VERSION 5.8 ;
BUSBITCHARS "[]" ;
DIVIDERCHAR "/" ;
UNITS
    DATABASE MICRONS 1000 ;
END UNITS

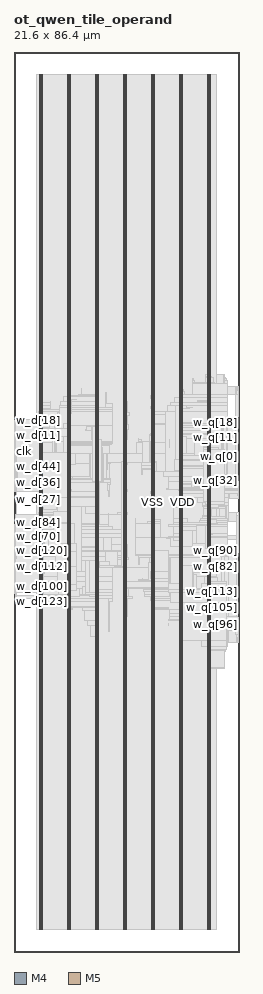
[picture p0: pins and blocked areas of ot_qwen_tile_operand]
MACRO ot_qwen_tile_operand
  FOREIGN ot_qwen_tile_operand 0 0 ;
  CLASS BLOCK ;
  SIZE 21.6 BY 86.4 ;
  PIN clk
    DIRECTION INPUT ;
    USE SIGNAL ;
    PORT
      LAYER M4 ;
        RECT  0 48.048 0.084 48.072 ;
    END
  END clk
  PIN gm_d[0]
    DIRECTION INPUT ;
    USE SIGNAL ;
    PORT
      LAYER M4 ;
        RECT  0 48.144 0.084 48.168 ;
    END
  END gm_d[0]
  PIN gm_d[1]
    DIRECTION INPUT ;
    USE SIGNAL ;
    PORT
      LAYER M4 ;
        RECT  0 48.24 0.084 48.264 ;
    END
  END gm_d[1]
  PIN gm_d[2]
    DIRECTION INPUT ;
    USE SIGNAL ;
    PORT
      LAYER M4 ;
        RECT  0 48.336 0.084 48.36 ;
    END
  END gm_d[2]
  PIN gm_d[3]
    DIRECTION INPUT ;
    USE SIGNAL ;
    PORT
      LAYER M4 ;
        RECT  0 48.432 0.084 48.456 ;
    END
  END gm_d[3]
  PIN w_d[0]
    DIRECTION INPUT ;
    USE SIGNAL ;
    PORT
      LAYER M4 ;
        RECT  0 48.528 0.084 48.552 ;
    END
  END w_d[0]
  PIN w_d[100]
    DIRECTION INPUT ;
    USE SIGNAL ;
    PORT
      LAYER M4 ;
        RECT  0 35.856 0.084 35.88 ;
    END
  END w_d[100]
  PIN w_d[101]
    DIRECTION INPUT ;
    USE SIGNAL ;
    PORT
      LAYER M4 ;
        RECT  0 35.952 0.084 35.976 ;
    END
  END w_d[101]
  PIN w_d[102]
    DIRECTION INPUT ;
    USE SIGNAL ;
    PORT
      LAYER M4 ;
        RECT  0 36.048 0.084 36.072 ;
    END
  END w_d[102]
  PIN w_d[103]
    DIRECTION INPUT ;
    USE SIGNAL ;
    PORT
      LAYER M4 ;
        RECT  0 36.144 0.084 36.168 ;
    END
  END w_d[103]
  PIN w_d[104]
    DIRECTION INPUT ;
    USE SIGNAL ;
    PORT
      LAYER M4 ;
        RECT  0 36.24 0.084 36.264 ;
    END
  END w_d[104]
  PIN w_d[105]
    DIRECTION INPUT ;
    USE SIGNAL ;
    PORT
      LAYER M4 ;
        RECT  0 36.336 0.084 36.36 ;
    END
  END w_d[105]
  PIN w_d[106]
    DIRECTION INPUT ;
    USE SIGNAL ;
    PORT
      LAYER M4 ;
        RECT  0 36.432 0.084 36.456 ;
    END
  END w_d[106]
  PIN w_d[107]
    DIRECTION INPUT ;
    USE SIGNAL ;
    PORT
      LAYER M4 ;
        RECT  0 36.528 0.084 36.552 ;
    END
  END w_d[107]
  PIN w_d[108]
    DIRECTION INPUT ;
    USE SIGNAL ;
    PORT
      LAYER M4 ;
        RECT  0 36.624 0.084 36.648 ;
    END
  END w_d[108]
  PIN w_d[109]
    DIRECTION INPUT ;
    USE SIGNAL ;
    PORT
      LAYER M4 ;
        RECT  0 36.72 0.084 36.744 ;
    END
  END w_d[109]
  PIN w_d[10]
    DIRECTION INPUT ;
    USE SIGNAL ;
    PORT
      LAYER M4 ;
        RECT  0 49.488 0.084 49.512 ;
    END
  END w_d[10]
  PIN w_d[110]
    DIRECTION INPUT ;
    USE SIGNAL ;
    PORT
      LAYER M4 ;
        RECT  0 36.816 0.084 36.84 ;
    END
  END w_d[110]
  PIN w_d[111]
    DIRECTION INPUT ;
    USE SIGNAL ;
    PORT
      LAYER M4 ;
        RECT  0 36.912 0.084 36.936 ;
    END
  END w_d[111]
  PIN w_d[112]
    DIRECTION INPUT ;
    USE SIGNAL ;
    PORT
      LAYER M4 ;
        RECT  0 37.008 0.084 37.032 ;
    END
  END w_d[112]
  PIN w_d[113]
    DIRECTION INPUT ;
    USE SIGNAL ;
    PORT
      LAYER M4 ;
        RECT  0 37.104 0.084 37.128 ;
    END
  END w_d[113]
  PIN w_d[114]
    DIRECTION INPUT ;
    USE SIGNAL ;
    PORT
      LAYER M4 ;
        RECT  0 37.2 0.084 37.224 ;
    END
  END w_d[114]
  PIN w_d[115]
    DIRECTION INPUT ;
    USE SIGNAL ;
    PORT
      LAYER M4 ;
        RECT  0 37.296 0.084 37.32 ;
    END
  END w_d[115]
  PIN w_d[116]
    DIRECTION INPUT ;
    USE SIGNAL ;
    PORT
      LAYER M4 ;
        RECT  0 37.392 0.084 37.416 ;
    END
  END w_d[116]
  PIN w_d[117]
    DIRECTION INPUT ;
    USE SIGNAL ;
    PORT
      LAYER M4 ;
        RECT  0 37.488 0.084 37.512 ;
    END
  END w_d[117]
  PIN w_d[118]
    DIRECTION INPUT ;
    USE SIGNAL ;
    PORT
      LAYER M4 ;
        RECT  0 37.584 0.084 37.608 ;
    END
  END w_d[118]
  PIN w_d[119]
    DIRECTION INPUT ;
    USE SIGNAL ;
    PORT
      LAYER M4 ;
        RECT  0 37.68 0.084 37.704 ;
    END
  END w_d[119]
  PIN w_d[11]
    DIRECTION INPUT ;
    USE SIGNAL ;
    PORT
      LAYER M4 ;
        RECT  0 49.584 0.084 49.608 ;
    END
  END w_d[11]
  PIN w_d[120]
    DIRECTION INPUT ;
    USE SIGNAL ;
    PORT
      LAYER M4 ;
        RECT  0 37.776 0.084 37.8 ;
    END
  END w_d[120]
  PIN w_d[121]
    DIRECTION INPUT ;
    USE SIGNAL ;
    PORT
      LAYER M4 ;
        RECT  0 37.872 0.084 37.896 ;
    END
  END w_d[121]
  PIN w_d[122]
    DIRECTION INPUT ;
    USE SIGNAL ;
    PORT
      LAYER M4 ;
        RECT  0 37.968 0.084 37.992 ;
    END
  END w_d[122]
  PIN w_d[123]
    DIRECTION INPUT ;
    USE SIGNAL ;
    PORT
      LAYER M4 ;
        RECT  0 34.416 0.084 34.44 ;
    END
  END w_d[123]
  PIN w_d[124]
    DIRECTION INPUT ;
    USE SIGNAL ;
    PORT
      LAYER M4 ;
        RECT  0 34.512 0.084 34.536 ;
    END
  END w_d[124]
  PIN w_d[125]
    DIRECTION INPUT ;
    USE SIGNAL ;
    PORT
      LAYER M4 ;
        RECT  0 34.608 0.084 34.632 ;
    END
  END w_d[125]
  PIN w_d[126]
    DIRECTION INPUT ;
    USE SIGNAL ;
    PORT
      LAYER M4 ;
        RECT  0 34.704 0.084 34.728 ;
    END
  END w_d[126]
  PIN w_d[127]
    DIRECTION INPUT ;
    USE SIGNAL ;
    PORT
      LAYER M4 ;
        RECT  0 34.8 0.084 34.824 ;
    END
  END w_d[127]
  PIN w_d[12]
    DIRECTION INPUT ;
    USE SIGNAL ;
    PORT
      LAYER M4 ;
        RECT  0 49.68 0.084 49.704 ;
    END
  END w_d[12]
  PIN w_d[13]
    DIRECTION INPUT ;
    USE SIGNAL ;
    PORT
      LAYER M4 ;
        RECT  0 49.776 0.084 49.8 ;
    END
  END w_d[13]
  PIN w_d[14]
    DIRECTION INPUT ;
    USE SIGNAL ;
    PORT
      LAYER M4 ;
        RECT  0 49.872 0.084 49.896 ;
    END
  END w_d[14]
  PIN w_d[15]
    DIRECTION INPUT ;
    USE SIGNAL ;
    PORT
      LAYER M4 ;
        RECT  0 49.968 0.084 49.992 ;
    END
  END w_d[15]
  PIN w_d[16]
    DIRECTION INPUT ;
    USE SIGNAL ;
    PORT
      LAYER M4 ;
        RECT  0 50.064 0.084 50.088 ;
    END
  END w_d[16]
  PIN w_d[17]
    DIRECTION INPUT ;
    USE SIGNAL ;
    PORT
      LAYER M4 ;
        RECT  0 50.16 0.084 50.184 ;
    END
  END w_d[17]
  PIN w_d[18]
    DIRECTION INPUT ;
    USE SIGNAL ;
    PORT
      LAYER M4 ;
        RECT  0 50.256 0.084 50.28 ;
    END
  END w_d[18]
  PIN w_d[19]
    DIRECTION INPUT ;
    USE SIGNAL ;
    PORT
      LAYER M4 ;
        RECT  0 50.352 0.084 50.376 ;
    END
  END w_d[19]
  PIN w_d[1]
    DIRECTION INPUT ;
    USE SIGNAL ;
    PORT
      LAYER M4 ;
        RECT  0 48.624 0.084 48.648 ;
    END
  END w_d[1]
  PIN w_d[20]
    DIRECTION INPUT ;
    USE SIGNAL ;
    PORT
      LAYER M4 ;
        RECT  0 50.448 0.084 50.472 ;
    END
  END w_d[20]
  PIN w_d[21]
    DIRECTION INPUT ;
    USE SIGNAL ;
    PORT
      LAYER M4 ;
        RECT  0 50.544 0.084 50.568 ;
    END
  END w_d[21]
  PIN w_d[22]
    DIRECTION INPUT ;
    USE SIGNAL ;
    PORT
      LAYER M4 ;
        RECT  0 50.64 0.084 50.664 ;
    END
  END w_d[22]
  PIN w_d[23]
    DIRECTION INPUT ;
    USE SIGNAL ;
    PORT
      LAYER M4 ;
        RECT  0 50.736 0.084 50.76 ;
    END
  END w_d[23]
  PIN w_d[24]
    DIRECTION INPUT ;
    USE SIGNAL ;
    PORT
      LAYER M4 ;
        RECT  0 50.832 0.084 50.856 ;
    END
  END w_d[24]
  PIN w_d[25]
    DIRECTION INPUT ;
    USE SIGNAL ;
    PORT
      LAYER M4 ;
        RECT  0 50.928 0.084 50.952 ;
    END
  END w_d[25]
  PIN w_d[26]
    DIRECTION INPUT ;
    USE SIGNAL ;
    PORT
      LAYER M4 ;
        RECT  0 51.024 0.084 51.048 ;
    END
  END w_d[26]
  PIN w_d[27]
    DIRECTION INPUT ;
    USE SIGNAL ;
    PORT
      LAYER M4 ;
        RECT  0 44.208 0.084 44.232 ;
    END
  END w_d[27]
  PIN w_d[28]
    DIRECTION INPUT ;
    USE SIGNAL ;
    PORT
      LAYER M4 ;
        RECT  0 44.304 0.084 44.328 ;
    END
  END w_d[28]
  PIN w_d[29]
    DIRECTION INPUT ;
    USE SIGNAL ;
    PORT
      LAYER M4 ;
        RECT  0 44.4 0.084 44.424 ;
    END
  END w_d[29]
  PIN w_d[2]
    DIRECTION INPUT ;
    USE SIGNAL ;
    PORT
      LAYER M4 ;
        RECT  0 48.72 0.084 48.744 ;
    END
  END w_d[2]
  PIN w_d[30]
    DIRECTION INPUT ;
    USE SIGNAL ;
    PORT
      LAYER M4 ;
        RECT  0 44.496 0.084 44.52 ;
    END
  END w_d[30]
  PIN w_d[31]
    DIRECTION INPUT ;
    USE SIGNAL ;
    PORT
      LAYER M4 ;
        RECT  0 44.592 0.084 44.616 ;
    END
  END w_d[31]
  PIN w_d[32]
    DIRECTION INPUT ;
    USE SIGNAL ;
    PORT
      LAYER M4 ;
        RECT  0 44.688 0.084 44.712 ;
    END
  END w_d[32]
  PIN w_d[33]
    DIRECTION INPUT ;
    USE SIGNAL ;
    PORT
      LAYER M4 ;
        RECT  0 44.784 0.084 44.808 ;
    END
  END w_d[33]
  PIN w_d[34]
    DIRECTION INPUT ;
    USE SIGNAL ;
    PORT
      LAYER M4 ;
        RECT  0 44.88 0.084 44.904 ;
    END
  END w_d[34]
  PIN w_d[35]
    DIRECTION INPUT ;
    USE SIGNAL ;
    PORT
      LAYER M4 ;
        RECT  0 44.976 0.084 45 ;
    END
  END w_d[35]
  PIN w_d[36]
    DIRECTION INPUT ;
    USE SIGNAL ;
    PORT
      LAYER M4 ;
        RECT  0 45.072 0.084 45.096 ;
    END
  END w_d[36]
  PIN w_d[37]
    DIRECTION INPUT ;
    USE SIGNAL ;
    PORT
      LAYER M4 ;
        RECT  0 45.168 0.084 45.192 ;
    END
  END w_d[37]
  PIN w_d[38]
    DIRECTION INPUT ;
    USE SIGNAL ;
    PORT
      LAYER M4 ;
        RECT  0 45.264 0.084 45.288 ;
    END
  END w_d[38]
  PIN w_d[39]
    DIRECTION INPUT ;
    USE SIGNAL ;
    PORT
      LAYER M4 ;
        RECT  0 45.36 0.084 45.384 ;
    END
  END w_d[39]
  PIN w_d[3]
    DIRECTION INPUT ;
    USE SIGNAL ;
    PORT
      LAYER M4 ;
        RECT  0 48.816 0.084 48.84 ;
    END
  END w_d[3]
  PIN w_d[40]
    DIRECTION INPUT ;
    USE SIGNAL ;
    PORT
      LAYER M4 ;
        RECT  0 45.456 0.084 45.48 ;
    END
  END w_d[40]
  PIN w_d[41]
    DIRECTION INPUT ;
    USE SIGNAL ;
    PORT
      LAYER M4 ;
        RECT  0 45.552 0.084 45.576 ;
    END
  END w_d[41]
  PIN w_d[42]
    DIRECTION INPUT ;
    USE SIGNAL ;
    PORT
      LAYER M4 ;
        RECT  0 45.648 0.084 45.672 ;
    END
  END w_d[42]
  PIN w_d[43]
    DIRECTION INPUT ;
    USE SIGNAL ;
    PORT
      LAYER M4 ;
        RECT  0 45.744 0.084 45.768 ;
    END
  END w_d[43]
  PIN w_d[44]
    DIRECTION INPUT ;
    USE SIGNAL ;
    PORT
      LAYER M4 ;
        RECT  0 45.84 0.084 45.864 ;
    END
  END w_d[44]
  PIN w_d[45]
    DIRECTION INPUT ;
    USE SIGNAL ;
    PORT
      LAYER M4 ;
        RECT  0 45.936 0.084 45.96 ;
    END
  END w_d[45]
  PIN w_d[46]
    DIRECTION INPUT ;
    USE SIGNAL ;
    PORT
      LAYER M4 ;
        RECT  0 46.032 0.084 46.056 ;
    END
  END w_d[46]
  PIN w_d[47]
    DIRECTION INPUT ;
    USE SIGNAL ;
    PORT
      LAYER M4 ;
        RECT  0 46.128 0.084 46.152 ;
    END
  END w_d[47]
  PIN w_d[48]
    DIRECTION INPUT ;
    USE SIGNAL ;
    PORT
      LAYER M4 ;
        RECT  0 46.224 0.084 46.248 ;
    END
  END w_d[48]
  PIN w_d[49]
    DIRECTION INPUT ;
    USE SIGNAL ;
    PORT
      LAYER M4 ;
        RECT  0 46.32 0.084 46.344 ;
    END
  END w_d[49]
  PIN w_d[4]
    DIRECTION INPUT ;
    USE SIGNAL ;
    PORT
      LAYER M4 ;
        RECT  0 48.912 0.084 48.936 ;
    END
  END w_d[4]
  PIN w_d[50]
    DIRECTION INPUT ;
    USE SIGNAL ;
    PORT
      LAYER M4 ;
        RECT  0 46.416 0.084 46.44 ;
    END
  END w_d[50]
  PIN w_d[51]
    DIRECTION INPUT ;
    USE SIGNAL ;
    PORT
      LAYER M4 ;
        RECT  0 46.512 0.084 46.536 ;
    END
  END w_d[51]
  PIN w_d[52]
    DIRECTION INPUT ;
    USE SIGNAL ;
    PORT
      LAYER M4 ;
        RECT  0 46.608 0.084 46.632 ;
    END
  END w_d[52]
  PIN w_d[53]
    DIRECTION INPUT ;
    USE SIGNAL ;
    PORT
      LAYER M4 ;
        RECT  0 46.704 0.084 46.728 ;
    END
  END w_d[53]
  PIN w_d[54]
    DIRECTION INPUT ;
    USE SIGNAL ;
    PORT
      LAYER M4 ;
        RECT  0 46.8 0.084 46.824 ;
    END
  END w_d[54]
  PIN w_d[55]
    DIRECTION INPUT ;
    USE SIGNAL ;
    PORT
      LAYER M4 ;
        RECT  0 46.896 0.084 46.92 ;
    END
  END w_d[55]
  PIN w_d[56]
    DIRECTION INPUT ;
    USE SIGNAL ;
    PORT
      LAYER M4 ;
        RECT  0 46.992 0.084 47.016 ;
    END
  END w_d[56]
  PIN w_d[57]
    DIRECTION INPUT ;
    USE SIGNAL ;
    PORT
      LAYER M4 ;
        RECT  0 47.088 0.084 47.112 ;
    END
  END w_d[57]
  PIN w_d[58]
    DIRECTION INPUT ;
    USE SIGNAL ;
    PORT
      LAYER M4 ;
        RECT  0 47.184 0.084 47.208 ;
    END
  END w_d[58]
  PIN w_d[59]
    DIRECTION INPUT ;
    USE SIGNAL ;
    PORT
      LAYER M4 ;
        RECT  0 38.064 0.084 38.088 ;
    END
  END w_d[59]
  PIN w_d[5]
    DIRECTION INPUT ;
    USE SIGNAL ;
    PORT
      LAYER M4 ;
        RECT  0 49.008 0.084 49.032 ;
    END
  END w_d[5]
  PIN w_d[60]
    DIRECTION INPUT ;
    USE SIGNAL ;
    PORT
      LAYER M4 ;
        RECT  0 38.16 0.084 38.184 ;
    END
  END w_d[60]
  PIN w_d[61]
    DIRECTION INPUT ;
    USE SIGNAL ;
    PORT
      LAYER M4 ;
        RECT  0 38.256 0.084 38.28 ;
    END
  END w_d[61]
  PIN w_d[62]
    DIRECTION INPUT ;
    USE SIGNAL ;
    PORT
      LAYER M4 ;
        RECT  0 38.352 0.084 38.376 ;
    END
  END w_d[62]
  PIN w_d[63]
    DIRECTION INPUT ;
    USE SIGNAL ;
    PORT
      LAYER M4 ;
        RECT  0 38.448 0.084 38.472 ;
    END
  END w_d[63]
  PIN w_d[64]
    DIRECTION INPUT ;
    USE SIGNAL ;
    PORT
      LAYER M4 ;
        RECT  0 38.544 0.084 38.568 ;
    END
  END w_d[64]
  PIN w_d[65]
    DIRECTION INPUT ;
    USE SIGNAL ;
    PORT
      LAYER M4 ;
        RECT  0 38.64 0.084 38.664 ;
    END
  END w_d[65]
  PIN w_d[66]
    DIRECTION INPUT ;
    USE SIGNAL ;
    PORT
      LAYER M4 ;
        RECT  0 38.736 0.084 38.76 ;
    END
  END w_d[66]
  PIN w_d[67]
    DIRECTION INPUT ;
    USE SIGNAL ;
    PORT
      LAYER M4 ;
        RECT  0 38.832 0.084 38.856 ;
    END
  END w_d[67]
  PIN w_d[68]
    DIRECTION INPUT ;
    USE SIGNAL ;
    PORT
      LAYER M4 ;
        RECT  0 38.928 0.084 38.952 ;
    END
  END w_d[68]
  PIN w_d[69]
    DIRECTION INPUT ;
    USE SIGNAL ;
    PORT
      LAYER M4 ;
        RECT  0 39.024 0.084 39.048 ;
    END
  END w_d[69]
  PIN w_d[6]
    DIRECTION INPUT ;
    USE SIGNAL ;
    PORT
      LAYER M4 ;
        RECT  0 49.104 0.084 49.128 ;
    END
  END w_d[6]
  PIN w_d[70]
    DIRECTION INPUT ;
    USE SIGNAL ;
    PORT
      LAYER M4 ;
        RECT  0 39.12 0.084 39.144 ;
    END
  END w_d[70]
  PIN w_d[71]
    DIRECTION INPUT ;
    USE SIGNAL ;
    PORT
      LAYER M4 ;
        RECT  0 39.216 0.084 39.24 ;
    END
  END w_d[71]
  PIN w_d[72]
    DIRECTION INPUT ;
    USE SIGNAL ;
    PORT
      LAYER M4 ;
        RECT  0 39.312 0.084 39.336 ;
    END
  END w_d[72]
  PIN w_d[73]
    DIRECTION INPUT ;
    USE SIGNAL ;
    PORT
      LAYER M4 ;
        RECT  0 39.408 0.084 39.432 ;
    END
  END w_d[73]
  PIN w_d[74]
    DIRECTION INPUT ;
    USE SIGNAL ;
    PORT
      LAYER M4 ;
        RECT  0 39.504 0.084 39.528 ;
    END
  END w_d[74]
  PIN w_d[75]
    DIRECTION INPUT ;
    USE SIGNAL ;
    PORT
      LAYER M4 ;
        RECT  0 39.6 0.084 39.624 ;
    END
  END w_d[75]
  PIN w_d[76]
    DIRECTION INPUT ;
    USE SIGNAL ;
    PORT
      LAYER M4 ;
        RECT  0 39.696 0.084 39.72 ;
    END
  END w_d[76]
  PIN w_d[77]
    DIRECTION INPUT ;
    USE SIGNAL ;
    PORT
      LAYER M4 ;
        RECT  0 39.792 0.084 39.816 ;
    END
  END w_d[77]
  PIN w_d[78]
    DIRECTION INPUT ;
    USE SIGNAL ;
    PORT
      LAYER M4 ;
        RECT  0 39.888 0.084 39.912 ;
    END
  END w_d[78]
  PIN w_d[79]
    DIRECTION INPUT ;
    USE SIGNAL ;
    PORT
      LAYER M4 ;
        RECT  0 39.984 0.084 40.008 ;
    END
  END w_d[79]
  PIN w_d[7]
    DIRECTION INPUT ;
    USE SIGNAL ;
    PORT
      LAYER M4 ;
        RECT  0 49.2 0.084 49.224 ;
    END
  END w_d[7]
  PIN w_d[80]
    DIRECTION INPUT ;
    USE SIGNAL ;
    PORT
      LAYER M4 ;
        RECT  0 40.08 0.084 40.104 ;
    END
  END w_d[80]
  PIN w_d[81]
    DIRECTION INPUT ;
    USE SIGNAL ;
    PORT
      LAYER M4 ;
        RECT  0 40.176 0.084 40.2 ;
    END
  END w_d[81]
  PIN w_d[82]
    DIRECTION INPUT ;
    USE SIGNAL ;
    PORT
      LAYER M4 ;
        RECT  0 40.272 0.084 40.296 ;
    END
  END w_d[82]
  PIN w_d[83]
    DIRECTION INPUT ;
    USE SIGNAL ;
    PORT
      LAYER M4 ;
        RECT  0 40.368 0.084 40.392 ;
    END
  END w_d[83]
  PIN w_d[84]
    DIRECTION INPUT ;
    USE SIGNAL ;
    PORT
      LAYER M4 ;
        RECT  0 40.464 0.084 40.488 ;
    END
  END w_d[84]
  PIN w_d[85]
    DIRECTION INPUT ;
    USE SIGNAL ;
    PORT
      LAYER M4 ;
        RECT  0 40.56 0.084 40.584 ;
    END
  END w_d[85]
  PIN w_d[86]
    DIRECTION INPUT ;
    USE SIGNAL ;
    PORT
      LAYER M4 ;
        RECT  0 40.656 0.084 40.68 ;
    END
  END w_d[86]
  PIN w_d[87]
    DIRECTION INPUT ;
    USE SIGNAL ;
    PORT
      LAYER M4 ;
        RECT  0 40.752 0.084 40.776 ;
    END
  END w_d[87]
  PIN w_d[88]
    DIRECTION INPUT ;
    USE SIGNAL ;
    PORT
      LAYER M4 ;
        RECT  0 40.848 0.084 40.872 ;
    END
  END w_d[88]
  PIN w_d[89]
    DIRECTION INPUT ;
    USE SIGNAL ;
    PORT
      LAYER M4 ;
        RECT  0 40.944 0.084 40.968 ;
    END
  END w_d[89]
  PIN w_d[8]
    DIRECTION INPUT ;
    USE SIGNAL ;
    PORT
      LAYER M4 ;
        RECT  0 49.296 0.084 49.32 ;
    END
  END w_d[8]
  PIN w_d[90]
    DIRECTION INPUT ;
    USE SIGNAL ;
    PORT
      LAYER M4 ;
        RECT  0 41.04 0.084 41.064 ;
    END
  END w_d[90]
  PIN w_d[91]
    DIRECTION INPUT ;
    USE SIGNAL ;
    PORT
      LAYER M4 ;
        RECT  0 34.992 0.084 35.016 ;
    END
  END w_d[91]
  PIN w_d[92]
    DIRECTION INPUT ;
    USE SIGNAL ;
    PORT
      LAYER M4 ;
        RECT  0 35.088 0.084 35.112 ;
    END
  END w_d[92]
  PIN w_d[93]
    DIRECTION INPUT ;
    USE SIGNAL ;
    PORT
      LAYER M4 ;
        RECT  0 35.184 0.084 35.208 ;
    END
  END w_d[93]
  PIN w_d[94]
    DIRECTION INPUT ;
    USE SIGNAL ;
    PORT
      LAYER M4 ;
        RECT  0 35.28 0.084 35.304 ;
    END
  END w_d[94]
  PIN w_d[95]
    DIRECTION INPUT ;
    USE SIGNAL ;
    PORT
      LAYER M4 ;
        RECT  0 35.376 0.084 35.4 ;
    END
  END w_d[95]
  PIN w_d[96]
    DIRECTION INPUT ;
    USE SIGNAL ;
    PORT
      LAYER M4 ;
        RECT  0 35.472 0.084 35.496 ;
    END
  END w_d[96]
  PIN w_d[97]
    DIRECTION INPUT ;
    USE SIGNAL ;
    PORT
      LAYER M4 ;
        RECT  0 35.568 0.084 35.592 ;
    END
  END w_d[97]
  PIN w_d[98]
    DIRECTION INPUT ;
    USE SIGNAL ;
    PORT
      LAYER M4 ;
        RECT  0 35.664 0.084 35.688 ;
    END
  END w_d[98]
  PIN w_d[99]
    DIRECTION INPUT ;
    USE SIGNAL ;
    PORT
      LAYER M4 ;
        RECT  0 35.76 0.084 35.784 ;
    END
  END w_d[99]
  PIN w_d[9]
    DIRECTION INPUT ;
    USE SIGNAL ;
    PORT
      LAYER M4 ;
        RECT  0 49.392 0.084 49.416 ;
    END
  END w_d[9]
  PIN w_q[0]
    DIRECTION OUTPUT ;
    USE SIGNAL ;
    PORT
      LAYER M4 ;
        RECT  21.516 48.336 21.6 48.36 ;
    END
  END w_q[0]
  PIN w_q[100]
    DIRECTION OUTPUT ;
    USE SIGNAL ;
    PORT
      LAYER M4 ;
        RECT  21.516 32.592 21.6 32.616 ;
    END
  END w_q[100]
  PIN w_q[101]
    DIRECTION OUTPUT ;
    USE SIGNAL ;
    PORT
      LAYER M4 ;
        RECT  21.516 32.688 21.6 32.712 ;
    END
  END w_q[101]
  PIN w_q[102]
    DIRECTION OUTPUT ;
    USE SIGNAL ;
    PORT
      LAYER M4 ;
        RECT  21.516 32.784 21.6 32.808 ;
    END
  END w_q[102]
  PIN w_q[103]
    DIRECTION OUTPUT ;
    USE SIGNAL ;
    PORT
      LAYER M4 ;
        RECT  21.516 32.88 21.6 32.904 ;
    END
  END w_q[103]
  PIN w_q[104]
    DIRECTION OUTPUT ;
    USE SIGNAL ;
    PORT
      LAYER M4 ;
        RECT  21.516 32.976 21.6 33 ;
    END
  END w_q[104]
  PIN w_q[105]
    DIRECTION OUTPUT ;
    USE SIGNAL ;
    PORT
      LAYER M4 ;
        RECT  21.516 33.072 21.6 33.096 ;
    END
  END w_q[105]
  PIN w_q[106]
    DIRECTION OUTPUT ;
    USE SIGNAL ;
    PORT
      LAYER M4 ;
        RECT  21.516 33.168 21.6 33.192 ;
    END
  END w_q[106]
  PIN w_q[107]
    DIRECTION OUTPUT ;
    USE SIGNAL ;
    PORT
      LAYER M4 ;
        RECT  21.516 33.264 21.6 33.288 ;
    END
  END w_q[107]
  PIN w_q[108]
    DIRECTION OUTPUT ;
    USE SIGNAL ;
    PORT
      LAYER M4 ;
        RECT  21.516 33.36 21.6 33.384 ;
    END
  END w_q[108]
  PIN w_q[109]
    DIRECTION OUTPUT ;
    USE SIGNAL ;
    PORT
      LAYER M4 ;
        RECT  21.516 33.456 21.6 33.48 ;
    END
  END w_q[109]
  PIN w_q[10]
    DIRECTION OUTPUT ;
    USE SIGNAL ;
    PORT
      LAYER M4 ;
        RECT  21.516 49.296 21.6 49.32 ;
    END
  END w_q[10]
  PIN w_q[110]
    DIRECTION OUTPUT ;
    USE SIGNAL ;
    PORT
      LAYER M4 ;
        RECT  21.516 33.552 21.6 33.576 ;
    END
  END w_q[110]
  PIN w_q[111]
    DIRECTION OUTPUT ;
    USE SIGNAL ;
    PORT
      LAYER M4 ;
        RECT  21.516 33.648 21.6 33.672 ;
    END
  END w_q[111]
  PIN w_q[112]
    DIRECTION OUTPUT ;
    USE SIGNAL ;
    PORT
      LAYER M4 ;
        RECT  21.516 33.744 21.6 33.768 ;
    END
  END w_q[112]
  PIN w_q[113]
    DIRECTION OUTPUT ;
    USE SIGNAL ;
    PORT
      LAYER M4 ;
        RECT  21.516 33.84 21.6 33.864 ;
    END
  END w_q[113]
  PIN w_q[114]
    DIRECTION OUTPUT ;
    USE SIGNAL ;
    PORT
      LAYER M4 ;
        RECT  21.516 33.936 21.6 33.96 ;
    END
  END w_q[114]
  PIN w_q[115]
    DIRECTION OUTPUT ;
    USE SIGNAL ;
    PORT
      LAYER M4 ;
        RECT  21.516 34.032 21.6 34.056 ;
    END
  END w_q[115]
  PIN w_q[116]
    DIRECTION OUTPUT ;
    USE SIGNAL ;
    PORT
      LAYER M4 ;
        RECT  21.516 34.128 21.6 34.152 ;
    END
  END w_q[116]
  PIN w_q[117]
    DIRECTION OUTPUT ;
    USE SIGNAL ;
    PORT
      LAYER M4 ;
        RECT  21.516 34.224 21.6 34.248 ;
    END
  END w_q[117]
  PIN w_q[118]
    DIRECTION OUTPUT ;
    USE SIGNAL ;
    PORT
      LAYER M4 ;
        RECT  21.516 34.32 21.6 34.344 ;
    END
  END w_q[118]
  PIN w_q[119]
    DIRECTION OUTPUT ;
    USE SIGNAL ;
    PORT
      LAYER M4 ;
        RECT  21.516 34.416 21.6 34.44 ;
    END
  END w_q[119]
  PIN w_q[11]
    DIRECTION OUTPUT ;
    USE SIGNAL ;
    PORT
      LAYER M4 ;
        RECT  21.516 49.392 21.6 49.416 ;
    END
  END w_q[11]
  PIN w_q[120]
    DIRECTION OUTPUT ;
    USE SIGNAL ;
    PORT
      LAYER M4 ;
        RECT  21.516 34.512 21.6 34.536 ;
    END
  END w_q[120]
  PIN w_q[121]
    DIRECTION OUTPUT ;
    USE SIGNAL ;
    PORT
      LAYER M4 ;
        RECT  21.516 34.608 21.6 34.632 ;
    END
  END w_q[121]
  PIN w_q[122]
    DIRECTION OUTPUT ;
    USE SIGNAL ;
    PORT
      LAYER M4 ;
        RECT  21.516 34.704 21.6 34.728 ;
    END
  END w_q[122]
  PIN w_q[123]
    DIRECTION OUTPUT ;
    USE SIGNAL ;
    PORT
      LAYER M4 ;
        RECT  21.516 34.8 21.6 34.824 ;
    END
  END w_q[123]
  PIN w_q[124]
    DIRECTION OUTPUT ;
    USE SIGNAL ;
    PORT
      LAYER M4 ;
        RECT  21.516 34.896 21.6 34.92 ;
    END
  END w_q[124]
  PIN w_q[125]
    DIRECTION OUTPUT ;
    USE SIGNAL ;
    PORT
      LAYER M4 ;
        RECT  21.516 34.992 21.6 35.016 ;
    END
  END w_q[125]
  PIN w_q[126]
    DIRECTION OUTPUT ;
    USE SIGNAL ;
    PORT
      LAYER M4 ;
        RECT  21.516 35.088 21.6 35.112 ;
    END
  END w_q[126]
  PIN w_q[127]
    DIRECTION OUTPUT ;
    USE SIGNAL ;
    PORT
      LAYER M4 ;
        RECT  21.516 35.184 21.6 35.208 ;
    END
  END w_q[127]
  PIN w_q[12]
    DIRECTION OUTPUT ;
    USE SIGNAL ;
    PORT
      LAYER M4 ;
        RECT  21.516 49.488 21.6 49.512 ;
    END
  END w_q[12]
  PIN w_q[13]
    DIRECTION OUTPUT ;
    USE SIGNAL ;
    PORT
      LAYER M4 ;
        RECT  21.516 49.584 21.6 49.608 ;
    END
  END w_q[13]
  PIN w_q[14]
    DIRECTION OUTPUT ;
    USE SIGNAL ;
    PORT
      LAYER M4 ;
        RECT  21.516 49.68 21.6 49.704 ;
    END
  END w_q[14]
  PIN w_q[15]
    DIRECTION OUTPUT ;
    USE SIGNAL ;
    PORT
      LAYER M4 ;
        RECT  21.516 49.776 21.6 49.8 ;
    END
  END w_q[15]
  PIN w_q[16]
    DIRECTION OUTPUT ;
    USE SIGNAL ;
    PORT
      LAYER M4 ;
        RECT  21.516 49.872 21.6 49.896 ;
    END
  END w_q[16]
  PIN w_q[17]
    DIRECTION OUTPUT ;
    USE SIGNAL ;
    PORT
      LAYER M4 ;
        RECT  21.516 49.968 21.6 49.992 ;
    END
  END w_q[17]
  PIN w_q[18]
    DIRECTION OUTPUT ;
    USE SIGNAL ;
    PORT
      LAYER M4 ;
        RECT  21.516 50.064 21.6 50.088 ;
    END
  END w_q[18]
  PIN w_q[19]
    DIRECTION OUTPUT ;
    USE SIGNAL ;
    PORT
      LAYER M4 ;
        RECT  21.516 50.16 21.6 50.184 ;
    END
  END w_q[19]
  PIN w_q[1]
    DIRECTION OUTPUT ;
    USE SIGNAL ;
    PORT
      LAYER M4 ;
        RECT  21.516 48.432 21.6 48.456 ;
    END
  END w_q[1]
  PIN w_q[20]
    DIRECTION OUTPUT ;
    USE SIGNAL ;
    PORT
      LAYER M4 ;
        RECT  21.516 50.256 21.6 50.28 ;
    END
  END w_q[20]
  PIN w_q[21]
    DIRECTION OUTPUT ;
    USE SIGNAL ;
    PORT
      LAYER M4 ;
        RECT  21.516 50.352 21.6 50.376 ;
    END
  END w_q[21]
  PIN w_q[22]
    DIRECTION OUTPUT ;
    USE SIGNAL ;
    PORT
      LAYER M4 ;
        RECT  21.516 50.448 21.6 50.472 ;
    END
  END w_q[22]
  PIN w_q[23]
    DIRECTION OUTPUT ;
    USE SIGNAL ;
    PORT
      LAYER M4 ;
        RECT  21.516 50.544 21.6 50.568 ;
    END
  END w_q[23]
  PIN w_q[24]
    DIRECTION OUTPUT ;
    USE SIGNAL ;
    PORT
      LAYER M4 ;
        RECT  21.516 50.64 21.6 50.664 ;
    END
  END w_q[24]
  PIN w_q[25]
    DIRECTION OUTPUT ;
    USE SIGNAL ;
    PORT
      LAYER M4 ;
        RECT  21.516 50.736 21.6 50.76 ;
    END
  END w_q[25]
  PIN w_q[26]
    DIRECTION OUTPUT ;
    USE SIGNAL ;
    PORT
      LAYER M4 ;
        RECT  21.516 50.832 21.6 50.856 ;
    END
  END w_q[26]
  PIN w_q[27]
    DIRECTION OUTPUT ;
    USE SIGNAL ;
    PORT
      LAYER M4 ;
        RECT  21.516 50.928 21.6 50.952 ;
    END
  END w_q[27]
  PIN w_q[28]
    DIRECTION OUTPUT ;
    USE SIGNAL ;
    PORT
      LAYER M4 ;
        RECT  21.516 51.024 21.6 51.048 ;
    END
  END w_q[28]
  PIN w_q[29]
    DIRECTION OUTPUT ;
    USE SIGNAL ;
    PORT
      LAYER M4 ;
        RECT  21.516 51.12 21.6 51.144 ;
    END
  END w_q[29]
  PIN w_q[2]
    DIRECTION OUTPUT ;
    USE SIGNAL ;
    PORT
      LAYER M4 ;
        RECT  21.516 48.528 21.6 48.552 ;
    END
  END w_q[2]
  PIN w_q[30]
    DIRECTION OUTPUT ;
    USE SIGNAL ;
    PORT
      LAYER M4 ;
        RECT  21.516 51.216 21.6 51.24 ;
    END
  END w_q[30]
  PIN w_q[31]
    DIRECTION OUTPUT ;
    USE SIGNAL ;
    PORT
      LAYER M4 ;
        RECT  21.516 51.312 21.6 51.336 ;
    END
  END w_q[31]
  PIN w_q[32]
    DIRECTION OUTPUT ;
    USE SIGNAL ;
    PORT
      LAYER M4 ;
        RECT  21.516 45.264 21.6 45.288 ;
    END
  END w_q[32]
  PIN w_q[33]
    DIRECTION OUTPUT ;
    USE SIGNAL ;
    PORT
      LAYER M4 ;
        RECT  21.516 45.36 21.6 45.384 ;
    END
  END w_q[33]
  PIN w_q[34]
    DIRECTION OUTPUT ;
    USE SIGNAL ;
    PORT
      LAYER M4 ;
        RECT  21.516 45.456 21.6 45.48 ;
    END
  END w_q[34]
  PIN w_q[35]
    DIRECTION OUTPUT ;
    USE SIGNAL ;
    PORT
      LAYER M4 ;
        RECT  21.516 45.552 21.6 45.576 ;
    END
  END w_q[35]
  PIN w_q[36]
    DIRECTION OUTPUT ;
    USE SIGNAL ;
    PORT
      LAYER M4 ;
        RECT  21.516 45.648 21.6 45.672 ;
    END
  END w_q[36]
  PIN w_q[37]
    DIRECTION OUTPUT ;
    USE SIGNAL ;
    PORT
      LAYER M4 ;
        RECT  21.516 45.744 21.6 45.768 ;
    END
  END w_q[37]
  PIN w_q[38]
    DIRECTION OUTPUT ;
    USE SIGNAL ;
    PORT
      LAYER M4 ;
        RECT  21.516 45.84 21.6 45.864 ;
    END
  END w_q[38]
  PIN w_q[39]
    DIRECTION OUTPUT ;
    USE SIGNAL ;
    PORT
      LAYER M4 ;
        RECT  21.516 45.936 21.6 45.96 ;
    END
  END w_q[39]
  PIN w_q[3]
    DIRECTION OUTPUT ;
    USE SIGNAL ;
    PORT
      LAYER M4 ;
        RECT  21.516 48.624 21.6 48.648 ;
    END
  END w_q[3]
  PIN w_q[40]
    DIRECTION OUTPUT ;
    USE SIGNAL ;
    PORT
      LAYER M4 ;
        RECT  21.516 46.032 21.6 46.056 ;
    END
  END w_q[40]
  PIN w_q[41]
    DIRECTION OUTPUT ;
    USE SIGNAL ;
    PORT
      LAYER M4 ;
        RECT  21.516 46.128 21.6 46.152 ;
    END
  END w_q[41]
  PIN w_q[42]
    DIRECTION OUTPUT ;
    USE SIGNAL ;
    PORT
      LAYER M4 ;
        RECT  21.516 46.224 21.6 46.248 ;
    END
  END w_q[42]
  PIN w_q[43]
    DIRECTION OUTPUT ;
    USE SIGNAL ;
    PORT
      LAYER M4 ;
        RECT  21.516 46.32 21.6 46.344 ;
    END
  END w_q[43]
  PIN w_q[44]
    DIRECTION OUTPUT ;
    USE SIGNAL ;
    PORT
      LAYER M4 ;
        RECT  21.516 46.416 21.6 46.44 ;
    END
  END w_q[44]
  PIN w_q[45]
    DIRECTION OUTPUT ;
    USE SIGNAL ;
    PORT
      LAYER M4 ;
        RECT  21.516 46.512 21.6 46.536 ;
    END
  END w_q[45]
  PIN w_q[46]
    DIRECTION OUTPUT ;
    USE SIGNAL ;
    PORT
      LAYER M4 ;
        RECT  21.516 46.608 21.6 46.632 ;
    END
  END w_q[46]
  PIN w_q[47]
    DIRECTION OUTPUT ;
    USE SIGNAL ;
    PORT
      LAYER M4 ;
        RECT  21.516 46.704 21.6 46.728 ;
    END
  END w_q[47]
  PIN w_q[48]
    DIRECTION OUTPUT ;
    USE SIGNAL ;
    PORT
      LAYER M4 ;
        RECT  21.516 46.8 21.6 46.824 ;
    END
  END w_q[48]
  PIN w_q[49]
    DIRECTION OUTPUT ;
    USE SIGNAL ;
    PORT
      LAYER M4 ;
        RECT  21.516 46.896 21.6 46.92 ;
    END
  END w_q[49]
  PIN w_q[4]
    DIRECTION OUTPUT ;
    USE SIGNAL ;
    PORT
      LAYER M4 ;
        RECT  21.516 48.72 21.6 48.744 ;
    END
  END w_q[4]
  PIN w_q[50]
    DIRECTION OUTPUT ;
    USE SIGNAL ;
    PORT
      LAYER M4 ;
        RECT  21.516 46.992 21.6 47.016 ;
    END
  END w_q[50]
  PIN w_q[51]
    DIRECTION OUTPUT ;
    USE SIGNAL ;
    PORT
      LAYER M4 ;
        RECT  21.516 47.088 21.6 47.112 ;
    END
  END w_q[51]
  PIN w_q[52]
    DIRECTION OUTPUT ;
    USE SIGNAL ;
    PORT
      LAYER M4 ;
        RECT  21.516 47.184 21.6 47.208 ;
    END
  END w_q[52]
  PIN w_q[53]
    DIRECTION OUTPUT ;
    USE SIGNAL ;
    PORT
      LAYER M4 ;
        RECT  21.516 47.28 21.6 47.304 ;
    END
  END w_q[53]
  PIN w_q[54]
    DIRECTION OUTPUT ;
    USE SIGNAL ;
    PORT
      LAYER M4 ;
        RECT  21.516 47.376 21.6 47.4 ;
    END
  END w_q[54]
  PIN w_q[55]
    DIRECTION OUTPUT ;
    USE SIGNAL ;
    PORT
      LAYER M4 ;
        RECT  21.516 47.472 21.6 47.496 ;
    END
  END w_q[55]
  PIN w_q[56]
    DIRECTION OUTPUT ;
    USE SIGNAL ;
    PORT
      LAYER M4 ;
        RECT  21.516 47.568 21.6 47.592 ;
    END
  END w_q[56]
  PIN w_q[57]
    DIRECTION OUTPUT ;
    USE SIGNAL ;
    PORT
      LAYER M4 ;
        RECT  21.516 47.664 21.6 47.688 ;
    END
  END w_q[57]
  PIN w_q[58]
    DIRECTION OUTPUT ;
    USE SIGNAL ;
    PORT
      LAYER M4 ;
        RECT  21.516 47.76 21.6 47.784 ;
    END
  END w_q[58]
  PIN w_q[59]
    DIRECTION OUTPUT ;
    USE SIGNAL ;
    PORT
      LAYER M4 ;
        RECT  21.516 47.856 21.6 47.88 ;
    END
  END w_q[59]
  PIN w_q[5]
    DIRECTION OUTPUT ;
    USE SIGNAL ;
    PORT
      LAYER M4 ;
        RECT  21.516 48.816 21.6 48.84 ;
    END
  END w_q[5]
  PIN w_q[60]
    DIRECTION OUTPUT ;
    USE SIGNAL ;
    PORT
      LAYER M4 ;
        RECT  21.516 47.952 21.6 47.976 ;
    END
  END w_q[60]
  PIN w_q[61]
    DIRECTION OUTPUT ;
    USE SIGNAL ;
    PORT
      LAYER M4 ;
        RECT  21.516 48.048 21.6 48.072 ;
    END
  END w_q[61]
  PIN w_q[62]
    DIRECTION OUTPUT ;
    USE SIGNAL ;
    PORT
      LAYER M4 ;
        RECT  21.516 48.144 21.6 48.168 ;
    END
  END w_q[62]
  PIN w_q[63]
    DIRECTION OUTPUT ;
    USE SIGNAL ;
    PORT
      LAYER M4 ;
        RECT  21.516 48.24 21.6 48.264 ;
    END
  END w_q[63]
  PIN w_q[64]
    DIRECTION OUTPUT ;
    USE SIGNAL ;
    PORT
      LAYER M4 ;
        RECT  21.516 35.28 21.6 35.304 ;
    END
  END w_q[64]
  PIN w_q[65]
    DIRECTION OUTPUT ;
    USE SIGNAL ;
    PORT
      LAYER M4 ;
        RECT  21.516 35.376 21.6 35.4 ;
    END
  END w_q[65]
  PIN w_q[66]
    DIRECTION OUTPUT ;
    USE SIGNAL ;
    PORT
      LAYER M4 ;
        RECT  21.516 35.472 21.6 35.496 ;
    END
  END w_q[66]
  PIN w_q[67]
    DIRECTION OUTPUT ;
    USE SIGNAL ;
    PORT
      LAYER M4 ;
        RECT  21.516 35.568 21.6 35.592 ;
    END
  END w_q[67]
  PIN w_q[68]
    DIRECTION OUTPUT ;
    USE SIGNAL ;
    PORT
      LAYER M4 ;
        RECT  21.516 35.664 21.6 35.688 ;
    END
  END w_q[68]
  PIN w_q[69]
    DIRECTION OUTPUT ;
    USE SIGNAL ;
    PORT
      LAYER M4 ;
        RECT  21.516 35.76 21.6 35.784 ;
    END
  END w_q[69]
  PIN w_q[6]
    DIRECTION OUTPUT ;
    USE SIGNAL ;
    PORT
      LAYER M4 ;
        RECT  21.516 48.912 21.6 48.936 ;
    END
  END w_q[6]
  PIN w_q[70]
    DIRECTION OUTPUT ;
    USE SIGNAL ;
    PORT
      LAYER M4 ;
        RECT  21.516 35.856 21.6 35.88 ;
    END
  END w_q[70]
  PIN w_q[71]
    DIRECTION OUTPUT ;
    USE SIGNAL ;
    PORT
      LAYER M4 ;
        RECT  21.516 35.952 21.6 35.976 ;
    END
  END w_q[71]
  PIN w_q[72]
    DIRECTION OUTPUT ;
    USE SIGNAL ;
    PORT
      LAYER M4 ;
        RECT  21.516 36.048 21.6 36.072 ;
    END
  END w_q[72]
  PIN w_q[73]
    DIRECTION OUTPUT ;
    USE SIGNAL ;
    PORT
      LAYER M4 ;
        RECT  21.516 36.144 21.6 36.168 ;
    END
  END w_q[73]
  PIN w_q[74]
    DIRECTION OUTPUT ;
    USE SIGNAL ;
    PORT
      LAYER M4 ;
        RECT  21.516 36.24 21.6 36.264 ;
    END
  END w_q[74]
  PIN w_q[75]
    DIRECTION OUTPUT ;
    USE SIGNAL ;
    PORT
      LAYER M4 ;
        RECT  21.516 36.336 21.6 36.36 ;
    END
  END w_q[75]
  PIN w_q[76]
    DIRECTION OUTPUT ;
    USE SIGNAL ;
    PORT
      LAYER M4 ;
        RECT  21.516 36.432 21.6 36.456 ;
    END
  END w_q[76]
  PIN w_q[77]
    DIRECTION OUTPUT ;
    USE SIGNAL ;
    PORT
      LAYER M4 ;
        RECT  21.516 36.528 21.6 36.552 ;
    END
  END w_q[77]
  PIN w_q[78]
    DIRECTION OUTPUT ;
    USE SIGNAL ;
    PORT
      LAYER M4 ;
        RECT  21.516 36.624 21.6 36.648 ;
    END
  END w_q[78]
  PIN w_q[79]
    DIRECTION OUTPUT ;
    USE SIGNAL ;
    PORT
      LAYER M4 ;
        RECT  21.516 36.72 21.6 36.744 ;
    END
  END w_q[79]
  PIN w_q[7]
    DIRECTION OUTPUT ;
    USE SIGNAL ;
    PORT
      LAYER M4 ;
        RECT  21.516 49.008 21.6 49.032 ;
    END
  END w_q[7]
  PIN w_q[80]
    DIRECTION OUTPUT ;
    USE SIGNAL ;
    PORT
      LAYER M4 ;
        RECT  21.516 36.816 21.6 36.84 ;
    END
  END w_q[80]
  PIN w_q[81]
    DIRECTION OUTPUT ;
    USE SIGNAL ;
    PORT
      LAYER M4 ;
        RECT  21.516 36.912 21.6 36.936 ;
    END
  END w_q[81]
  PIN w_q[82]
    DIRECTION OUTPUT ;
    USE SIGNAL ;
    PORT
      LAYER M4 ;
        RECT  21.516 37.008 21.6 37.032 ;
    END
  END w_q[82]
  PIN w_q[83]
    DIRECTION OUTPUT ;
    USE SIGNAL ;
    PORT
      LAYER M4 ;
        RECT  21.516 37.104 21.6 37.128 ;
    END
  END w_q[83]
  PIN w_q[84]
    DIRECTION OUTPUT ;
    USE SIGNAL ;
    PORT
      LAYER M4 ;
        RECT  21.516 37.2 21.6 37.224 ;
    END
  END w_q[84]
  PIN w_q[85]
    DIRECTION OUTPUT ;
    USE SIGNAL ;
    PORT
      LAYER M4 ;
        RECT  21.516 37.296 21.6 37.32 ;
    END
  END w_q[85]
  PIN w_q[86]
    DIRECTION OUTPUT ;
    USE SIGNAL ;
    PORT
      LAYER M4 ;
        RECT  21.516 37.392 21.6 37.416 ;
    END
  END w_q[86]
  PIN w_q[87]
    DIRECTION OUTPUT ;
    USE SIGNAL ;
    PORT
      LAYER M4 ;
        RECT  21.516 37.488 21.6 37.512 ;
    END
  END w_q[87]
  PIN w_q[88]
    DIRECTION OUTPUT ;
    USE SIGNAL ;
    PORT
      LAYER M4 ;
        RECT  21.516 37.584 21.6 37.608 ;
    END
  END w_q[88]
  PIN w_q[89]
    DIRECTION OUTPUT ;
    USE SIGNAL ;
    PORT
      LAYER M4 ;
        RECT  21.516 37.68 21.6 37.704 ;
    END
  END w_q[89]
  PIN w_q[8]
    DIRECTION OUTPUT ;
    USE SIGNAL ;
    PORT
      LAYER M4 ;
        RECT  21.516 49.104 21.6 49.128 ;
    END
  END w_q[8]
  PIN w_q[90]
    DIRECTION OUTPUT ;
    USE SIGNAL ;
    PORT
      LAYER M4 ;
        RECT  21.516 37.776 21.6 37.8 ;
    END
  END w_q[90]
  PIN w_q[91]
    DIRECTION OUTPUT ;
    USE SIGNAL ;
    PORT
      LAYER M4 ;
        RECT  21.516 37.872 21.6 37.896 ;
    END
  END w_q[91]
  PIN w_q[92]
    DIRECTION OUTPUT ;
    USE SIGNAL ;
    PORT
      LAYER M4 ;
        RECT  21.516 37.968 21.6 37.992 ;
    END
  END w_q[92]
  PIN w_q[93]
    DIRECTION OUTPUT ;
    USE SIGNAL ;
    PORT
      LAYER M4 ;
        RECT  21.516 38.064 21.6 38.088 ;
    END
  END w_q[93]
  PIN w_q[94]
    DIRECTION OUTPUT ;
    USE SIGNAL ;
    PORT
      LAYER M4 ;
        RECT  21.516 38.16 21.6 38.184 ;
    END
  END w_q[94]
  PIN w_q[95]
    DIRECTION OUTPUT ;
    USE SIGNAL ;
    PORT
      LAYER M4 ;
        RECT  21.516 38.256 21.6 38.28 ;
    END
  END w_q[95]
  PIN w_q[96]
    DIRECTION OUTPUT ;
    USE SIGNAL ;
    PORT
      LAYER M4 ;
        RECT  21.516 32.208 21.6 32.232 ;
    END
  END w_q[96]
  PIN w_q[97]
    DIRECTION OUTPUT ;
    USE SIGNAL ;
    PORT
      LAYER M4 ;
        RECT  21.516 32.304 21.6 32.328 ;
    END
  END w_q[97]
  PIN w_q[98]
    DIRECTION OUTPUT ;
    USE SIGNAL ;
    PORT
      LAYER M4 ;
        RECT  21.516 32.4 21.6 32.424 ;
    END
  END w_q[98]
  PIN w_q[99]
    DIRECTION OUTPUT ;
    USE SIGNAL ;
    PORT
      LAYER M4 ;
        RECT  21.516 32.496 21.6 32.52 ;
    END
  END w_q[99]
  PIN w_q[9]
    DIRECTION OUTPUT ;
    USE SIGNAL ;
    PORT
      LAYER M4 ;
        RECT  21.516 49.2 21.6 49.224 ;
    END
  END w_q[9]
  PIN wsrc_d
    DIRECTION INPUT ;
    USE SIGNAL ;
    PORT
      LAYER M4 ;
        RECT  0 34.896 0.084 34.92 ;
    END
  END wsrc_d
  PIN VDD
    DIRECTION INOUT ;
    USE POWER ;
    PORT
      LAYER M5 ;
        RECT  18.792 2.151 18.912 84.249 ;
        RECT  16.092 2.151 16.212 84.249 ;
        RECT  13.392 2.151 13.512 84.249 ;
        RECT  10.692 2.151 10.812 84.249 ;
        RECT  7.992 2.151 8.112 84.249 ;
        RECT  5.292 2.151 5.412 84.249 ;
        RECT  2.592 2.151 2.712 84.249 ;
    END
  END VDD
  PIN VSS
    DIRECTION INOUT ;
    USE GROUND ;
    PORT
      LAYER M5 ;
        RECT  18.6 2.137 18.72 84.263 ;
        RECT  15.9 2.137 16.02 84.263 ;
        RECT  13.2 2.137 13.32 84.263 ;
        RECT  10.5 2.137 10.62 84.263 ;
        RECT  7.8 2.137 7.92 84.263 ;
        RECT  5.1 2.137 5.22 84.263 ;
        RECT  2.4 2.137 2.52 84.263 ;
    END
  END VSS
  OBS
    LAYER RVTN ;
     RECT  2.16 2.16 19.44 2.295 ;
     RECT  2.16 2.565 19.44 2.835 ;
     RECT  2.16 3.105 19.44 3.375 ;
     RECT  2.16 3.645 19.44 3.915 ;
     RECT  2.16 4.185 19.44 4.455 ;
     RECT  2.16 4.725 19.44 4.995 ;
     RECT  2.16 5.265 19.44 5.535 ;
     RECT  2.16 5.805 19.44 6.075 ;
     RECT  2.16 6.345 19.44 6.615 ;
     RECT  2.16 6.885 19.44 7.155 ;
     RECT  2.16 7.425 19.44 7.695 ;
     RECT  2.16 7.965 19.44 8.235 ;
     RECT  2.16 8.505 19.44 8.775 ;
     RECT  2.16 9.045 19.44 9.315 ;
     RECT  2.16 9.585 19.44 9.855 ;
     RECT  2.16 10.125 19.44 10.395 ;
     RECT  2.16 10.665 19.44 10.935 ;
     RECT  2.16 11.205 19.44 11.475 ;
     RECT  2.16 11.745 19.44 12.015 ;
     RECT  2.16 12.285 19.44 12.555 ;
     RECT  2.16 12.825 19.44 13.095 ;
     RECT  2.16 13.365 19.44 13.635 ;
     RECT  2.16 13.905 19.44 14.175 ;
     RECT  2.16 14.445 19.44 14.715 ;
     RECT  2.16 14.985 19.44 15.255 ;
     RECT  2.16 15.525 19.44 15.795 ;
     RECT  2.16 16.065 19.44 16.335 ;
     RECT  2.16 16.605 19.44 16.875 ;
     RECT  2.16 17.145 19.44 17.415 ;
     RECT  2.16 17.685 19.44 17.955 ;
     RECT  2.16 18.225 19.44 18.495 ;
     RECT  2.16 18.765 19.44 19.035 ;
     RECT  2.16 19.305 19.44 19.575 ;
     RECT  2.16 19.845 19.44 20.115 ;
     RECT  2.16 20.385 19.44 20.655 ;
     RECT  2.16 20.925 19.44 21.195 ;
     RECT  2.16 21.465 19.44 21.735 ;
     RECT  2.16 22.005 19.44 22.275 ;
     RECT  2.16 22.545 19.44 22.815 ;
     RECT  2.16 23.085 19.44 23.355 ;
     RECT  2.16 23.625 19.44 23.895 ;
     RECT  2.16 24.165 19.44 24.435 ;
     RECT  2.16 24.705 19.44 24.975 ;
     RECT  2.16 25.245 19.44 25.515 ;
     RECT  2.16 25.785 19.44 26.055 ;
     RECT  2.16 26.325 19.44 26.595 ;
     RECT  2.16 26.865 19.44 27.135 ;
     RECT  2.16 27.405 19.44 27.675 ;
     RECT  2.16 27.945 19.44 28.215 ;
     RECT  2.16 28.485 19.44 28.755 ;
     RECT  2.16 29.025 19.44 29.295 ;
     RECT  2.16 29.565 19.44 29.835 ;
     RECT  2.16 30.105 19.44 30.375 ;
     RECT  2.16 30.645 19.44 30.915 ;
     RECT  2.16 31.185 19.44 31.455 ;
     RECT  2.16 31.725 19.44 31.995 ;
     RECT  2.16 32.265 19.44 32.535 ;
     RECT  2.16 32.805 19.44 33.075 ;
     RECT  2.16 33.345 19.44 33.615 ;
     RECT  2.16 33.885 19.44 34.155 ;
     RECT  2.16 34.425 19.44 34.695 ;
     RECT  2.16 34.965 19.44 35.235 ;
     RECT  2.16 35.505 19.44 35.775 ;
     RECT  2.16 36.045 19.44 36.315 ;
     RECT  2.16 36.585 19.44 36.855 ;
     RECT  2.16 37.125 19.44 37.395 ;
     RECT  2.16 37.665 19.44 37.935 ;
     RECT  2.16 38.205 19.44 38.475 ;
     RECT  2.16 38.745 19.44 39.015 ;
     RECT  2.16 39.285 19.44 39.555 ;
     RECT  2.16 39.825 19.44 40.095 ;
     RECT  2.16 40.365 19.44 40.635 ;
     RECT  2.16 40.905 19.44 41.175 ;
     RECT  2.16 41.445 19.44 41.715 ;
     RECT  2.16 41.985 19.44 42.255 ;
     RECT  2.16 42.525 19.44 42.795 ;
     RECT  2.16 43.065 19.44 43.335 ;
     RECT  2.16 43.605 19.44 43.875 ;
     RECT  2.16 44.145 19.44 44.415 ;
     RECT  2.16 44.685 19.44 44.955 ;
     RECT  2.16 45.225 19.44 45.495 ;
     RECT  2.16 45.765 19.44 46.035 ;
     RECT  2.16 46.305 19.44 46.575 ;
     RECT  2.16 46.845 19.44 47.115 ;
     RECT  2.16 47.385 19.44 47.655 ;
     RECT  2.16 47.925 19.44 48.195 ;
     RECT  2.16 48.465 19.44 48.735 ;
     RECT  2.16 49.005 19.44 49.275 ;
     RECT  2.16 49.545 19.44 49.815 ;
     RECT  2.16 50.085 19.44 50.355 ;
     RECT  2.16 50.625 19.44 50.895 ;
     RECT  2.16 51.165 19.44 51.435 ;
     RECT  2.16 51.705 19.44 51.975 ;
     RECT  2.16 52.245 19.44 52.515 ;
     RECT  2.16 52.785 19.44 53.055 ;
     RECT  2.16 53.325 19.44 53.595 ;
     RECT  2.16 53.865 19.44 54.135 ;
     RECT  2.16 54.405 19.44 54.675 ;
     RECT  2.16 54.945 19.44 55.215 ;
     RECT  2.16 55.485 19.44 55.755 ;
     RECT  2.16 56.025 19.44 56.295 ;
     RECT  2.16 56.565 19.44 56.835 ;
     RECT  2.16 57.105 19.44 57.375 ;
     RECT  2.16 57.645 19.44 57.915 ;
     RECT  2.16 58.185 19.44 58.455 ;
     RECT  2.16 58.725 19.44 58.995 ;
     RECT  2.16 59.265 19.44 59.535 ;
     RECT  2.16 59.805 19.44 60.075 ;
     RECT  2.16 60.345 19.44 60.615 ;
     RECT  2.16 60.885 19.44 61.155 ;
     RECT  2.16 61.425 19.44 61.695 ;
     RECT  2.16 61.965 19.44 62.235 ;
     RECT  2.16 62.505 19.44 62.775 ;
     RECT  2.16 63.045 19.44 63.315 ;
     RECT  2.16 63.585 19.44 63.855 ;
     RECT  2.16 64.125 19.44 64.395 ;
     RECT  2.16 64.665 19.44 64.935 ;
     RECT  2.16 65.205 19.44 65.475 ;
     RECT  2.16 65.745 19.44 66.015 ;
     RECT  2.16 66.285 19.44 66.555 ;
     RECT  2.16 66.825 19.44 67.095 ;
     RECT  2.16 67.365 19.44 67.635 ;
     RECT  2.16 67.905 19.44 68.175 ;
     RECT  2.16 68.445 19.44 68.715 ;
     RECT  2.16 68.985 19.44 69.255 ;
     RECT  2.16 69.525 19.44 69.795 ;
     RECT  2.16 70.065 19.44 70.335 ;
     RECT  2.16 70.605 19.44 70.875 ;
     RECT  2.16 71.145 19.44 71.415 ;
     RECT  2.16 71.685 19.44 71.955 ;
     RECT  2.16 72.225 19.44 72.495 ;
     RECT  2.16 72.765 19.44 73.035 ;
     RECT  2.16 73.305 19.44 73.575 ;
     RECT  2.16 73.845 19.44 74.115 ;
     RECT  2.16 74.385 19.44 74.655 ;
     RECT  2.16 74.925 19.44 75.195 ;
     RECT  2.16 75.465 19.44 75.735 ;
     RECT  2.16 76.005 19.44 76.275 ;
     RECT  2.16 76.545 19.44 76.815 ;
     RECT  2.16 77.085 19.44 77.355 ;
     RECT  2.16 77.625 19.44 77.895 ;
     RECT  2.16 78.165 19.44 78.435 ;
     RECT  2.16 78.705 19.44 78.975 ;
     RECT  2.16 79.245 19.44 79.515 ;
     RECT  2.16 79.785 19.44 80.055 ;
     RECT  2.16 80.325 19.44 80.595 ;
     RECT  2.16 80.865 19.44 81.135 ;
     RECT  2.16 81.405 19.44 81.675 ;
     RECT  2.16 81.945 19.44 82.215 ;
     RECT  2.16 82.485 19.44 82.755 ;
     RECT  2.16 83.025 19.44 83.295 ;
     RECT  2.16 83.565 19.44 83.835 ;
     RECT  2.16 84.105 19.44 84.24 ;
    LAYER RVTP ;
     RECT  2.16 2.295 19.44 2.565 ;
     RECT  2.16 2.835 19.44 3.105 ;
     RECT  2.16 3.375 19.44 3.645 ;
     RECT  2.16 3.915 19.44 4.185 ;
     RECT  2.16 4.455 19.44 4.725 ;
     RECT  2.16 4.995 19.44 5.265 ;
     RECT  2.16 5.535 19.44 5.805 ;
     RECT  2.16 6.075 19.44 6.345 ;
     RECT  2.16 6.615 19.44 6.885 ;
     RECT  2.16 7.155 19.44 7.425 ;
     RECT  2.16 7.695 19.44 7.965 ;
     RECT  2.16 8.235 19.44 8.505 ;
     RECT  2.16 8.775 19.44 9.045 ;
     RECT  2.16 9.315 19.44 9.585 ;
     RECT  2.16 9.855 19.44 10.125 ;
     RECT  2.16 10.395 19.44 10.665 ;
     RECT  2.16 10.935 19.44 11.205 ;
     RECT  2.16 11.475 19.44 11.745 ;
     RECT  2.16 12.015 19.44 12.285 ;
     RECT  2.16 12.555 19.44 12.825 ;
     RECT  2.16 13.095 19.44 13.365 ;
     RECT  2.16 13.635 19.44 13.905 ;
     RECT  2.16 14.175 19.44 14.445 ;
     RECT  2.16 14.715 19.44 14.985 ;
     RECT  2.16 15.255 19.44 15.525 ;
     RECT  2.16 15.795 19.44 16.065 ;
     RECT  2.16 16.335 19.44 16.605 ;
     RECT  2.16 16.875 19.44 17.145 ;
     RECT  2.16 17.415 19.44 17.685 ;
     RECT  2.16 17.955 19.44 18.225 ;
     RECT  2.16 18.495 19.44 18.765 ;
     RECT  2.16 19.035 19.44 19.305 ;
     RECT  2.16 19.575 19.44 19.845 ;
     RECT  2.16 20.115 19.44 20.385 ;
     RECT  2.16 20.655 19.44 20.925 ;
     RECT  2.16 21.195 19.44 21.465 ;
     RECT  2.16 21.735 19.44 22.005 ;
     RECT  2.16 22.275 19.44 22.545 ;
     RECT  2.16 22.815 19.44 23.085 ;
     RECT  2.16 23.355 19.44 23.625 ;
     RECT  2.16 23.895 19.44 24.165 ;
     RECT  2.16 24.435 19.44 24.705 ;
     RECT  2.16 24.975 19.44 25.245 ;
     RECT  2.16 25.515 19.44 25.785 ;
     RECT  2.16 26.055 19.44 26.325 ;
     RECT  2.16 26.595 19.44 26.865 ;
     RECT  2.16 27.135 19.44 27.405 ;
     RECT  2.16 27.675 19.44 27.945 ;
     RECT  2.16 28.215 19.44 28.485 ;
     RECT  2.16 28.755 19.44 29.025 ;
     RECT  2.16 29.295 19.44 29.565 ;
     RECT  2.16 29.835 19.44 30.105 ;
     RECT  2.16 30.375 19.44 30.645 ;
     RECT  2.16 30.915 19.44 31.185 ;
     RECT  2.16 31.455 19.44 31.725 ;
     RECT  2.16 31.995 19.44 32.265 ;
     RECT  2.16 32.535 19.44 32.805 ;
     RECT  2.16 33.075 19.44 33.345 ;
     RECT  2.16 33.615 19.44 33.885 ;
     RECT  2.16 34.155 19.44 34.425 ;
     RECT  2.16 34.695 19.44 34.965 ;
     RECT  2.16 35.235 19.44 35.505 ;
     RECT  2.16 35.775 19.44 36.045 ;
     RECT  2.16 36.315 19.44 36.585 ;
     RECT  2.16 36.855 19.44 37.125 ;
     RECT  2.16 37.395 19.44 37.665 ;
     RECT  2.16 37.935 19.44 38.205 ;
     RECT  2.16 38.475 19.44 38.745 ;
     RECT  2.16 39.015 19.44 39.285 ;
     RECT  2.16 39.555 19.44 39.825 ;
     RECT  2.16 40.095 19.44 40.365 ;
     RECT  2.16 40.635 19.44 40.905 ;
     RECT  2.16 41.175 19.44 41.445 ;
     RECT  2.16 41.715 19.44 41.985 ;
     RECT  2.16 42.255 19.44 42.525 ;
     RECT  2.16 42.795 19.44 43.065 ;
     RECT  2.16 43.335 19.44 43.605 ;
     RECT  2.16 43.875 19.44 44.145 ;
     RECT  2.16 44.415 19.44 44.685 ;
     RECT  2.16 44.955 19.44 45.225 ;
     RECT  2.16 45.495 19.44 45.765 ;
     RECT  2.16 46.035 19.44 46.305 ;
     RECT  2.16 46.575 19.44 46.845 ;
     RECT  2.16 47.115 19.44 47.385 ;
     RECT  2.16 47.655 19.44 47.925 ;
     RECT  2.16 48.195 19.44 48.465 ;
     RECT  2.16 48.735 19.44 49.005 ;
     RECT  2.16 49.275 19.44 49.545 ;
     RECT  2.16 49.815 19.44 50.085 ;
     RECT  2.16 50.355 19.44 50.625 ;
     RECT  2.16 50.895 19.44 51.165 ;
     RECT  2.16 51.435 19.44 51.705 ;
     RECT  2.16 51.975 19.44 52.245 ;
     RECT  2.16 52.515 19.44 52.785 ;
     RECT  2.16 53.055 19.44 53.325 ;
     RECT  2.16 53.595 19.44 53.865 ;
     RECT  2.16 54.135 19.44 54.405 ;
     RECT  2.16 54.675 19.44 54.945 ;
     RECT  2.16 55.215 19.44 55.485 ;
     RECT  2.16 55.755 19.44 56.025 ;
     RECT  2.16 56.295 19.44 56.565 ;
     RECT  2.16 56.835 19.44 57.105 ;
     RECT  2.16 57.375 19.44 57.645 ;
     RECT  2.16 57.915 19.44 58.185 ;
     RECT  2.16 58.455 19.44 58.725 ;
     RECT  2.16 58.995 19.44 59.265 ;
     RECT  2.16 59.535 19.44 59.805 ;
     RECT  2.16 60.075 19.44 60.345 ;
     RECT  2.16 60.615 19.44 60.885 ;
     RECT  2.16 61.155 19.44 61.425 ;
     RECT  2.16 61.695 19.44 61.965 ;
     RECT  2.16 62.235 19.44 62.505 ;
     RECT  2.16 62.775 19.44 63.045 ;
     RECT  2.16 63.315 19.44 63.585 ;
     RECT  2.16 63.855 19.44 64.125 ;
     RECT  2.16 64.395 19.44 64.665 ;
     RECT  2.16 64.935 19.44 65.205 ;
     RECT  2.16 65.475 19.44 65.745 ;
     RECT  2.16 66.015 19.44 66.285 ;
     RECT  2.16 66.555 19.44 66.825 ;
     RECT  2.16 67.095 19.44 67.365 ;
     RECT  2.16 67.635 19.44 67.905 ;
     RECT  2.16 68.175 19.44 68.445 ;
     RECT  2.16 68.715 19.44 68.985 ;
     RECT  2.16 69.255 19.44 69.525 ;
     RECT  2.16 69.795 19.44 70.065 ;
     RECT  2.16 70.335 19.44 70.605 ;
     RECT  2.16 70.875 19.44 71.145 ;
     RECT  2.16 71.415 19.44 71.685 ;
     RECT  2.16 71.955 19.44 72.225 ;
     RECT  2.16 72.495 19.44 72.765 ;
     RECT  2.16 73.035 19.44 73.305 ;
     RECT  2.16 73.575 19.44 73.845 ;
     RECT  2.16 74.115 19.44 74.385 ;
     RECT  2.16 74.655 19.44 74.925 ;
     RECT  2.16 75.195 19.44 75.465 ;
     RECT  2.16 75.735 19.44 76.005 ;
     RECT  2.16 76.275 19.44 76.545 ;
     RECT  2.16 76.815 19.44 77.085 ;
     RECT  2.16 77.355 19.44 77.625 ;
     RECT  2.16 77.895 19.44 78.165 ;
     RECT  2.16 78.435 19.44 78.705 ;
     RECT  2.16 78.975 19.44 79.245 ;
     RECT  2.16 79.515 19.44 79.785 ;
     RECT  2.16 80.055 19.44 80.325 ;
     RECT  2.16 80.595 19.44 80.865 ;
     RECT  2.16 81.135 19.44 81.405 ;
     RECT  2.16 81.675 19.44 81.945 ;
     RECT  2.16 82.215 19.44 82.485 ;
     RECT  2.16 82.755 19.44 83.025 ;
     RECT  2.16 83.295 19.44 83.565 ;
     RECT  2.16 83.835 19.44 84.105 ;
    LAYER M1 ;
     RECT  2.16 2.151 19.44 84.249 ;
    LAYER M2 ;
     RECT  0.103 34.092 0.139 34.11 ;
     RECT  0.139 33.93 0.175 34.11 ;
     RECT  0.103 46.386 0.175 46.602 ;
     RECT  0.175 46.242 0.247 46.674 ;
     RECT  0.103 37.944 0.347 37.962 ;
     RECT  0.247 46.242 0.347 46.719 ;
     RECT  0.347 46.656 0.383 46.719 ;
     RECT  0.383 46.701 0.419 46.719 ;
     RECT  1.723 41.382 1.759 41.4 ;
     RECT  0.175 33.93 2.16 34.182 ;
     RECT  1.759 41.382 2.16 41.742 ;
     RECT  0.103 44.352 2.16 44.37 ;
     RECT  0.535 48.276 2.16 48.294 ;
     RECT  2.16 2.151 19.44 84.249 ;
     RECT  19.44 28.8 19.463 31.716 ;
     RECT  19.44 32.616 19.535 35.154 ;
     RECT  19.44 45.936 19.535 48.564 ;
     RECT  19.535 32.616 19.571 33.804 ;
     RECT  19.463 28.836 19.607 31.716 ;
     RECT  19.535 45.936 19.607 46.719 ;
     RECT  19.607 28.836 19.643 31.644 ;
     RECT  19.643 28.836 19.931 31.482 ;
     RECT  19.607 45.936 19.931 46.602 ;
     RECT  19.571 32.616 19.967 33.174 ;
     RECT  19.535 47.556 19.967 48.564 ;
     RECT  19.967 32.616 20.003 32.634 ;
     RECT  19.931 45.936 20.075 46.134 ;
     RECT  19.44 52.83 20.147 55.404 ;
     RECT  20.147 53.298 20.255 55.404 ;
     RECT  19.931 28.836 20.291 31.284 ;
     RECT  20.255 53.298 20.327 55.134 ;
     RECT  19.44 39.564 20.399 44.946 ;
     RECT  20.327 53.298 20.399 55.044 ;
     RECT  19.44 37.026 20.435 37.044 ;
     RECT  19.44 38.106 20.435 38.466 ;
     RECT  20.399 53.298 20.435 54.864 ;
     RECT  20.291 29.376 20.471 31.284 ;
     RECT  20.435 53.496 20.471 54.864 ;
     RECT  20.471 29.736 20.507 31.284 ;
     RECT  19.535 35.136 20.507 35.154 ;
     RECT  19.44 36.126 20.507 36.144 ;
     RECT  20.435 38.106 20.507 38.196 ;
     RECT  20.399 39.564 20.507 40.194 ;
     RECT  20.075 46.116 20.507 46.134 ;
     RECT  19.44 50.526 20.507 51.084 ;
     RECT  19.967 48.006 20.543 48.564 ;
     RECT  20.507 29.736 20.579 31.104 ;
     RECT  20.507 38.178 20.579 38.196 ;
     RECT  20.399 41.346 20.615 44.946 ;
     RECT  20.615 43.578 20.651 44.946 ;
     RECT  20.471 53.496 21.299 54.324 ;
     RECT  20.579 29.736 21.371 30.834 ;
     RECT  21.299 53.676 21.371 54.324 ;
     RECT  20.615 41.346 21.407 42.174 ;
     RECT  21.371 53.838 21.407 54.324 ;
     RECT  21.407 41.346 21.443 41.364 ;
     RECT  21.407 54.036 21.443 54.324 ;
     RECT  20.507 50.796 21.451 51.084 ;
     RECT  21.371 29.736 21.479 30.636 ;
     RECT  20.507 39.564 21.479 40.014 ;
     RECT  21.479 29.736 21.515 29.934 ;
     RECT  21.479 39.564 21.515 39.582 ;
     RECT  20.651 43.578 21.515 44.334 ;
     RECT  21.451 50.67 21.515 51.084 ;
     RECT  21.515 43.578 21.551 43.596 ;
     RECT  21.451 46.782 21.551 46.8 ;
     RECT  21.515 29.736 21.587 29.754 ;
     RECT  21.487 34.128 21.587 34.146 ;
     RECT  21.379 38.106 21.587 38.124 ;
     RECT  21.407 42.156 21.587 42.174 ;
     RECT  21.515 50.67 21.587 50.688 ;
     RECT  21.443 54.306 21.587 54.324 ;
    LAYER M3 ;
     RECT  2.415 2.143 2.505 2.413 ;
     RECT  5.115 2.143 5.205 2.413 ;
     RECT  7.815 2.143 7.905 2.413 ;
     RECT  10.515 2.143 10.605 2.413 ;
     RECT  13.215 2.143 13.305 2.413 ;
     RECT  15.915 2.143 16.005 2.413 ;
     RECT  18.615 2.143 18.705 2.413 ;
     RECT  18.615 2.413 18.897 27.259 ;
     RECT  18.615 27.259 19.242 27.329 ;
     RECT  18.615 27.329 19.062 27.365 ;
     RECT  18.615 27.365 18.897 28.759 ;
     RECT  18.615 28.759 19.314 28.795 ;
     RECT  18.615 28.795 19.458 28.957 ;
     RECT  20.268 28.831 20.286 28.957 ;
     RECT  18.576 28.957 19.458 29.029 ;
     RECT  20.196 28.957 20.286 29.029 ;
     RECT  18.576 29.029 20.286 29.335 ;
     RECT  18.504 29.335 20.286 29.371 ;
     RECT  18.504 29.371 20.466 29.875 ;
     RECT  21.564 29.731 21.582 29.911 ;
     RECT  18.252 29.875 20.466 30.145 ;
     RECT  21.492 29.911 21.582 30.145 ;
     RECT  7.815 2.413 8.097 30.307 ;
     RECT  18.036 30.145 20.466 30.307 ;
     RECT  15.915 2.413 16.197 30.451 ;
     RECT  17.496 30.307 20.466 30.451 ;
     RECT  21.312 30.145 21.582 30.451 ;
     RECT  15.915 30.451 16.686 30.541 ;
     RECT  17.46 30.451 20.466 30.541 ;
     RECT  15.915 30.541 20.466 30.883 ;
     RECT  15.915 30.883 20.538 31.081 ;
     RECT  21.276 30.451 21.582 31.081 ;
     RECT  9.108 30.811 9.126 31.189 ;
     RECT  7.344 30.307 8.097 31.387 ;
     RECT  14.832 31.387 14.85 31.559 ;
     RECT  7.056 31.387 8.097 31.801 ;
     RECT  15.915 31.081 21.582 31.801 ;
     RECT  14.868 31.801 21.582 31.919 ;
     RECT  10.515 2.413 10.797 32.161 ;
     RECT  14.904 31.919 21.582 32.525 ;
     RECT  6.732 31.801 8.097 32.737 ;
     RECT  13.215 2.413 13.497 32.845 ;
     RECT  10.515 32.161 10.926 32.873 ;
     RECT  5.115 2.413 5.397 32.881 ;
     RECT  13.215 32.845 13.842 32.881 ;
     RECT  14.904 32.525 20.538 32.881 ;
     RECT  5.115 32.881 5.634 32.971 ;
     RECT  21.276 32.525 21.582 33.005 ;
     RECT  5.076 32.971 5.634 33.007 ;
     RECT  4.896 33.007 5.634 33.043 ;
     RECT  6.588 32.737 8.097 33.043 ;
     RECT  4.896 33.043 8.097 33.151 ;
     RECT  3.528 33.421 3.546 33.691 ;
     RECT  4.32 33.151 8.097 33.691 ;
     RECT  9.072 31.189 9.126 33.691 ;
     RECT  13.215 32.881 20.538 33.781 ;
     RECT  3.528 33.691 8.097 33.889 ;
     RECT  9.072 33.691 9.414 33.889 ;
     RECT  10.515 32.873 10.89 33.889 ;
     RECT  2.415 2.413 2.697 33.925 ;
     RECT  3.528 33.889 9.414 33.925 ;
     RECT  10.515 33.889 10.926 33.925 ;
     RECT  10.515 33.925 10.998 33.961 ;
     RECT  13.104 33.781 20.538 33.965 ;
     RECT  0.144 33.925 0.162 34.087 ;
     RECT  10.515 33.961 11.394 34.115 ;
     RECT  13.104 33.965 20.358 34.123 ;
     RECT  21.348 33.005 21.582 34.151 ;
     RECT  0.108 34.087 0.162 34.159 ;
     RECT  21.348 34.151 21.51 34.16 ;
     RECT  2.415 33.925 9.414 34.231 ;
     RECT  12.528 34.123 20.358 34.357 ;
     RECT  0.108 34.159 0.198 34.445 ;
     RECT  21.348 34.16 21.366 34.445 ;
     RECT  2.304 34.231 9.414 34.465 ;
     RECT  12.492 34.357 20.358 34.627 ;
     RECT  0.144 34.445 0.198 34.637 ;
     RECT  0.18 34.637 0.198 34.733 ;
     RECT  12.42 34.627 20.358 34.795 ;
     RECT  2.268 34.465 9.414 34.799 ;
     RECT  10.515 34.115 10.998 34.933 ;
     RECT  12.42 34.795 20.502 34.933 ;
     RECT  10.515 34.933 20.502 35.021 ;
     RECT  20.484 35.021 20.502 35.159 ;
     RECT  2.268 34.799 4.23 35.545 ;
     RECT  5.076 34.799 9.414 35.545 ;
     RECT  10.515 35.021 19.674 35.573 ;
     RECT  10.515 35.573 12.366 35.609 ;
     RECT  21.42 35.515 21.438 35.693 ;
     RECT  11.988 35.609 12.366 35.771 ;
     RECT  0.144 35.515 0.162 35.789 ;
     RECT  13.104 35.573 19.674 35.851 ;
     RECT  20.448 35.755 20.466 35.851 ;
     RECT  12.348 35.771 12.366 35.879 ;
     RECT  13.104 35.851 20.466 35.947 ;
     RECT  2.268 35.545 9.414 36.077 ;
     RECT  13.104 35.947 20.502 36.475 ;
     RECT  0.144 36.715 0.162 36.893 ;
     RECT  2.304 36.077 9.414 36.907 ;
     RECT  10.515 35.609 10.797 36.907 ;
     RECT  2.304 36.907 10.797 37.121 ;
     RECT  2.304 37.121 9.162 37.129 ;
     RECT  21.456 36.715 21.474 37.387 ;
     RECT  2.232 37.129 9.162 37.463 ;
     RECT  9.936 37.121 10.797 37.633 ;
     RECT  9.936 37.633 10.854 37.705 ;
     RECT  11.988 37.165 12.006 37.831 ;
     RECT  12.96 36.475 20.502 37.831 ;
     RECT  9.936 37.705 10.962 37.859 ;
     RECT  0.324 37.771 0.342 37.867 ;
     RECT  21.456 37.387 21.51 37.867 ;
     RECT  2.232 37.463 8.802 37.931 ;
     RECT  0.108 37.867 0.342 37.967 ;
     RECT  0.144 37.967 0.342 37.997 ;
     RECT  9.936 37.859 10.926 38.039 ;
     RECT  21.42 37.867 21.51 38.059 ;
     RECT  11.988 37.831 20.502 38.101 ;
     RECT  21.384 38.059 21.51 38.101 ;
     RECT  11.664 38.101 20.502 38.155 ;
     RECT  11.664 38.155 20.574 38.201 ;
     RECT  2.268 37.931 8.802 38.443 ;
     RECT  9.936 38.039 10.854 38.443 ;
     RECT  2.268 38.443 10.854 38.543 ;
     RECT  0.144 37.997 0.162 38.717 ;
     RECT  0.216 38.923 0.342 39.053 ;
     RECT  9.396 38.543 10.854 39.083 ;
     RECT  0.216 39.053 0.234 39.341 ;
     RECT  2.268 38.543 8.622 39.757 ;
     RECT  9.396 39.083 10.797 39.757 ;
     RECT  11.664 38.201 20.502 39.773 ;
     RECT  14.832 39.773 20.502 39.893 ;
     RECT  0.324 39.883 0.342 40.109 ;
     RECT  2.268 39.757 10.797 40.171 ;
     RECT  15.336 39.893 20.502 40.199 ;
     RECT  1.728 40.171 10.797 40.559 ;
     RECT  15.336 40.199 20.466 40.801 ;
     RECT  1.728 40.559 9.414 40.829 ;
     RECT  1.728 40.829 9.09 41.009 ;
     RECT  14.832 40.801 20.466 41.009 ;
     RECT  11.664 39.773 14.022 41.099 ;
     RECT  0.108 41.035 0.126 41.213 ;
     RECT  15.336 41.009 20.466 41.279 ;
     RECT  12.816 41.099 14.022 41.369 ;
     RECT  1.728 41.009 8.226 41.405 ;
     RECT  17.784 41.279 20.466 41.405 ;
     RECT  13.215 41.369 14.022 41.477 ;
     RECT  11.664 41.099 11.682 41.639 ;
     RECT  15.336 41.279 16.614 41.639 ;
     RECT  17.892 41.405 20.466 41.639 ;
     RECT  1.764 41.405 8.226 41.747 ;
     RECT  18.072 41.639 20.286 41.783 ;
     RECT  21.384 38.101 21.582 41.909 ;
     RECT  2.304 41.747 8.226 41.945 ;
     RECT  18.072 41.783 18.99 41.945 ;
     RECT  10.515 40.559 10.797 41.995 ;
     RECT  9.072 41.009 9.09 42.089 ;
     RECT  9.972 41.995 10.854 42.179 ;
     RECT  21.564 41.909 21.582 42.179 ;
     RECT  2.376 41.945 8.226 42.215 ;
     RECT  2.415 42.215 8.226 42.449 ;
     RECT  2.415 42.449 3.222 42.485 ;
     RECT  18.18 41.945 18.99 42.601 ;
     RECT  19.764 41.783 20.286 42.601 ;
     RECT  2.415 42.485 2.79 42.629 ;
     RECT  15.336 41.639 16.197 42.719 ;
     RECT  18.18 42.601 20.286 42.763 ;
     RECT  18.108 42.763 20.286 42.871 ;
     RECT  18.108 42.871 20.61 43.105 ;
     RECT  15.915 42.719 16.197 43.573 ;
     RECT  4.032 42.449 8.226 43.645 ;
     RECT  15.915 43.573 16.83 43.645 ;
     RECT  17.568 43.105 20.61 43.645 ;
     RECT  2.415 42.629 2.697 43.681 ;
     RECT  3.42 43.645 8.226 43.681 ;
     RECT  21.528 43.573 21.546 43.843 ;
     RECT  9.108 43.771 9.126 44.041 ;
     RECT  13.215 41.477 13.497 44.041 ;
     RECT  15.915 43.645 20.61 44.041 ;
     RECT  21.42 43.843 21.546 44.041 ;
     RECT  2.415 43.681 8.226 44.185 ;
     RECT  13.104 44.041 13.497 44.213 ;
     RECT  10.515 42.179 10.797 44.221 ;
     RECT  15.915 44.041 21.546 44.311 ;
     RECT  9.036 44.041 9.126 44.347 ;
     RECT  10.515 44.221 10.854 44.411 ;
     RECT  15.804 44.311 21.546 44.443 ;
     RECT  14.616 44.443 21.546 44.483 ;
     RECT  0.108 44.347 0.126 44.621 ;
     RECT  10.515 44.411 10.818 44.879 ;
     RECT  9 44.347 9.126 44.923 ;
     RECT  0.144 44.779 0.162 44.957 ;
     RECT  2.304 44.185 8.226 45.031 ;
     RECT  9 44.923 9.306 45.031 ;
     RECT  2.304 45.031 9.306 45.355 ;
     RECT  2.268 45.355 9.306 45.419 ;
     RECT  14.832 44.483 21.546 45.661 ;
     RECT  0.18 46.219 0.198 46.237 ;
     RECT  12.276 45.841 12.366 46.309 ;
     RECT  13.215 44.213 13.497 46.309 ;
     RECT  0.18 46.237 0.342 46.315 ;
     RECT  10.515 44.879 10.797 46.381 ;
     RECT  12.276 46.309 13.497 46.381 ;
     RECT  14.364 45.661 21.546 46.381 ;
     RECT  0.108 46.315 0.342 46.555 ;
     RECT  0.108 46.555 0.414 46.724 ;
     RECT  0.108 46.724 0.378 46.733 ;
     RECT  12.276 46.381 21.546 46.733 ;
     RECT  10.515 46.381 10.818 46.777 ;
     RECT  21.456 46.733 21.546 46.805 ;
     RECT  21.456 46.805 21.474 46.829 ;
     RECT  2.268 45.419 9.198 46.849 ;
     RECT  10.515 46.777 10.854 46.849 ;
     RECT  10.515 46.849 10.926 46.921 ;
     RECT  2.268 46.849 9.306 46.949 ;
     RECT  10.44 46.921 10.926 47.035 ;
     RECT  10.224 47.035 10.926 47.111 ;
     RECT  12.276 46.733 20.718 47.155 ;
     RECT  0.108 46.733 0.198 47.165 ;
     RECT  0.108 47.165 0.126 47.309 ;
     RECT  10.44 47.111 10.926 47.309 ;
     RECT  12.132 47.155 20.718 47.309 ;
     RECT  2.268 46.949 9.198 47.345 ;
     RECT  10.515 47.309 10.926 47.587 ;
     RECT  12.132 47.309 20.538 47.659 ;
     RECT  11.772 47.659 20.538 47.695 ;
     RECT  10.515 47.587 10.962 47.759 ;
     RECT  11.736 47.695 20.538 47.885 ;
     RECT  2.304 47.345 9.198 48.619 ;
     RECT  2.268 48.619 9.198 48.703 ;
     RECT  0.54 48.271 0.558 48.749 ;
     RECT  2.268 48.703 9.378 48.811 ;
     RECT  20.34 47.885 20.538 48.845 ;
     RECT  2.268 48.811 9.414 48.907 ;
     RECT  20.34 48.845 20.394 48.907 ;
     RECT  11.736 47.885 19.458 48.929 ;
     RECT  2.196 48.907 9.414 48.965 ;
     RECT  11.952 48.929 19.458 49.003 ;
     RECT  20.196 48.907 20.394 49.003 ;
     RECT  11.952 49.003 20.394 49.037 ;
     RECT  21.312 48.715 21.33 49.099 ;
     RECT  11.952 49.037 12.258 49.235 ;
     RECT  10.515 47.759 10.797 49.243 ;
     RECT  11.952 49.235 11.97 49.343 ;
     RECT  21.312 49.099 21.438 49.483 ;
     RECT  0.144 49.387 0.162 49.565 ;
     RECT  10.515 49.243 10.854 49.576 ;
     RECT  12.996 49.037 20.394 49.649 ;
     RECT  13.104 49.649 20.394 49.771 ;
     RECT  13.104 49.771 20.43 49.775 ;
     RECT  10.515 49.576 10.89 49.891 ;
     RECT  13.176 49.775 20.43 50.059 ;
     RECT  10.515 49.891 10.926 50.161 ;
     RECT  13.176 50.059 20.502 50.333 ;
     RECT  21.312 49.483 21.51 50.443 ;
     RECT  13.212 50.333 20.502 50.549 ;
     RECT  2.268 48.965 9.414 50.585 ;
     RECT  10.515 50.161 10.962 50.657 ;
     RECT  21.276 50.443 21.51 50.665 ;
     RECT  13.212 50.549 20.466 50.693 ;
     RECT  0.324 50.731 0.342 50.923 ;
     RECT  0.108 50.923 0.342 50.957 ;
     RECT  0.108 50.957 0.126 51.149 ;
     RECT  10.515 50.657 10.926 51.511 ;
     RECT  10.515 51.511 11.07 51.773 ;
     RECT  10.515 51.773 10.962 51.809 ;
     RECT  2.304 50.585 9.414 51.935 ;
     RECT  13.215 50.693 20.466 51.935 ;
     RECT  2.415 51.935 9.414 52.079 ;
     RECT  2.415 52.079 3.546 52.169 ;
     RECT  13.215 51.935 13.497 52.177 ;
     RECT  4.356 52.079 9.414 52.313 ;
     RECT  13.104 52.177 13.497 52.349 ;
     RECT  2.415 52.169 3.51 52.439 ;
     RECT  4.356 52.313 8.097 52.475 ;
     RECT  14.76 51.935 20.466 52.475 ;
     RECT  8.82 52.313 9.414 52.619 ;
     RECT  2.415 52.439 3.474 52.709 ;
     RECT  15.048 52.475 20.466 52.709 ;
     RECT  4.428 52.475 8.097 52.853 ;
     RECT  3.456 52.709 3.474 52.889 ;
     RECT  10.515 51.809 10.854 52.889 ;
     RECT  8.82 52.619 8.91 52.979 ;
     RECT  13.215 52.349 13.497 53.131 ;
     RECT  15.408 52.709 20.466 53.249 ;
     RECT  4.716 52.853 8.097 53.321 ;
     RECT  13.104 53.131 13.497 53.393 ;
     RECT  5.115 53.321 8.097 53.429 ;
     RECT  5.115 53.429 5.454 53.519 ;
     RECT  6.228 53.429 8.097 53.519 ;
     RECT  21.276 50.665 21.582 53.519 ;
     RECT  15.876 53.249 20.466 53.555 ;
     RECT  8.82 52.979 8.838 53.699 ;
     RECT  15.915 53.555 16.362 53.789 ;
     RECT  21.312 53.519 21.582 53.897 ;
     RECT  15.915 53.789 16.254 53.969 ;
     RECT  6.444 53.519 6.462 54.059 ;
     RECT  21.42 53.897 21.582 54.059 ;
     RECT  15.915 53.969 16.218 54.095 ;
     RECT  21.564 54.059 21.582 54.329 ;
     RECT  17.172 53.555 20.466 54.599 ;
     RECT  17.172 54.599 19.278 54.635 ;
     RECT  17.172 54.635 17.37 54.671 ;
     RECT  18.396 54.635 19.278 54.707 ;
     RECT  17.172 54.671 17.334 54.869 ;
     RECT  20.16 54.599 20.466 54.869 ;
     RECT  17.172 54.869 17.19 55.049 ;
     RECT  20.16 54.869 20.394 55.049 ;
     RECT  20.16 55.049 20.322 55.139 ;
     RECT  18.396 54.707 19.17 55.175 ;
     RECT  18.396 55.175 18.954 55.211 ;
     RECT  20.16 55.139 20.25 55.283 ;
     RECT  20.232 55.283 20.25 55.409 ;
     RECT  18.396 55.211 18.897 55.445 ;
     RECT  2.415 52.709 2.697 83.987 ;
     RECT  5.115 53.519 5.397 83.987 ;
     RECT  7.815 53.519 8.097 83.987 ;
     RECT  10.515 52.889 10.797 83.987 ;
     RECT  13.215 53.393 13.497 83.987 ;
     RECT  15.915 54.095 16.197 83.987 ;
     RECT  18.615 55.445 18.897 83.987 ;
     RECT  2.415 83.987 2.505 84.257 ;
     RECT  5.115 83.987 5.205 84.257 ;
     RECT  7.815 83.987 7.905 84.257 ;
     RECT  10.515 83.987 10.605 84.257 ;
     RECT  13.215 83.987 13.305 84.257 ;
     RECT  15.915 83.987 16.005 84.257 ;
     RECT  18.615 83.987 18.705 84.257 ;
    LAYER M4 ;
     RECT  0.06 34.416 0.097 41.064 ;
     RECT  0.06 44.208 0.097 51.048 ;
     RECT  0.097 34.416 0.137 41.208 ;
     RECT  0.137 34.512 0.181 41.208 ;
     RECT  0.181 34.512 2.408 42.024 ;
     RECT  0.097 44.208 2.408 51.144 ;
     RECT  2.408 2.148 2.512 84.252 ;
     RECT  2.512 2.418 2.704 83.982 ;
     RECT  2.704 34.32 2.765 40.584 ;
     RECT  2.765 34.32 2.873 40.392 ;
     RECT  2.873 36.336 2.909 37.416 ;
     RECT  2.873 38.448 2.909 40.392 ;
     RECT  2.704 43.68 2.909 51.336 ;
     RECT  2.909 36.96 2.945 37.416 ;
     RECT  2.909 38.688 3.269 40.392 ;
     RECT  2.909 43.68 3.683 45.096 ;
     RECT  3.269 40.08 3.788 40.392 ;
     RECT  2.704 42 3.788 42.216 ;
     RECT  3.788 40.08 3.829 42.216 ;
     RECT  2.909 46.224 3.877 51.336 ;
     RECT  2.945 36.96 3.913 37.032 ;
     RECT  3.269 38.688 3.925 38.76 ;
     RECT  3.913 36.96 3.949 37.08 ;
     RECT  3.925 38.4 3.949 38.76 ;
     RECT  3.877 45.936 3.971 51.336 ;
     RECT  3.971 45.936 4.061 49.08 ;
     RECT  3.829 40.08 4.165 42.264 ;
     RECT  3.683 43.68 4.165 44.472 ;
     RECT  3.971 50.256 4.201 51.336 ;
     RECT  4.165 40.08 4.237 44.472 ;
     RECT  4.201 50.256 4.345 51.768 ;
     RECT  4.061 45.936 4.777 49.032 ;
     RECT  4.237 39.84 4.981 44.472 ;
     RECT  4.777 45.552 5.101 49.032 ;
     RECT  2.873 34.32 5.108 35.352 ;
     RECT  3.949 36.624 5.108 38.76 ;
     RECT  4.981 39.792 5.108 44.472 ;
     RECT  5.101 45.504 5.108 49.032 ;
     RECT  4.345 50.256 5.108 52.296 ;
     RECT  5.108 2.148 5.212 84.252 ;
     RECT  5.212 2.418 5.404 83.982 ;
     RECT  5.404 44.352 5.501 44.376 ;
     RECT  5.404 49.008 5.501 49.032 ;
     RECT  5.404 51.744 5.501 53.064 ;
     RECT  5.501 52.272 5.555 53.064 ;
     RECT  5.404 45.504 5.573 45.672 ;
     RECT  5.404 46.848 5.897 47.88 ;
     RECT  5.555 53.04 6.041 53.064 ;
     RECT  5.404 34.128 6.257 34.872 ;
     RECT  5.404 36.528 6.437 42.792 ;
     RECT  6.437 38.688 6.473 42.792 ;
     RECT  6.473 40.32 6.509 42.792 ;
     RECT  6.257 34.368 6.577 34.872 ;
     RECT  6.577 34.368 6.829 35.112 ;
     RECT  6.437 36.528 6.829 37.608 ;
     RECT  6.901 50.112 6.937 50.136 ;
     RECT  6.829 34.368 7.261 37.608 ;
     RECT  5.573 45.648 7.261 45.672 ;
     RECT  5.897 46.944 7.261 47.88 ;
     RECT  7.261 45.648 7.369 47.88 ;
     RECT  6.937 50.112 7.477 50.424 ;
     RECT  7.369 45.456 7.513 47.88 ;
     RECT  7.477 49.2 7.513 50.424 ;
     RECT  7.513 45.456 7.549 50.424 ;
     RECT  6.469 33.072 7.808 33.096 ;
     RECT  7.261 34.128 7.808 37.608 ;
     RECT  6.473 38.88 7.808 38.904 ;
     RECT  6.509 41.184 7.808 42.792 ;
     RECT  7.549 45.216 7.808 50.424 ;
     RECT  7.808 2.148 7.912 84.252 ;
     RECT  7.912 2.418 8.104 83.982 ;
     RECT  8.104 36.912 8.237 37.464 ;
     RECT  8.104 45.216 8.381 49.224 ;
     RECT  8.381 45.216 8.489 48.456 ;
     RECT  8.489 45.216 8.597 47.88 ;
     RECT  8.597 45.504 8.885 47.88 ;
     RECT  8.885 46.32 8.957 47.88 ;
     RECT  8.237 36.912 9.673 36.936 ;
     RECT  9.673 36.912 10.508 37.032 ;
     RECT  8.104 42 10.508 42.024 ;
     RECT  8.957 47.04 10.508 47.88 ;
     RECT  10.508 2.148 10.612 84.252 ;
     RECT  10.612 2.418 10.804 83.982 ;
     RECT  10.804 42 10.865 42.024 ;
     RECT  10.804 34.128 11.009 34.152 ;
     RECT  10.804 47.04 12.301 47.88 ;
     RECT  12.229 49.008 12.301 49.032 ;
     RECT  11.977 35.712 12.949 35.736 ;
     RECT  10.804 36.912 12.949 36.936 ;
     RECT  12.301 47.04 13.045 49.032 ;
     RECT  13.045 47.04 13.093 49.56 ;
     RECT  13.093 47.04 13.165 49.8 ;
     RECT  13.165 47.04 13.201 50.328 ;
     RECT  12.949 35.712 13.208 37.368 ;
     RECT  13.201 47.04 13.208 50.664 ;
     RECT  13.208 2.148 13.312 84.252 ;
     RECT  13.312 2.418 13.504 83.982 ;
     RECT  13.504 48.912 14.533 50.664 ;
     RECT  13.504 51.648 14.533 51.864 ;
     RECT  13.504 46.128 14.569 47.88 ;
     RECT  14.533 48.912 14.569 51.864 ;
     RECT  14.605 44.448 14.821 44.472 ;
     RECT  13.504 33.024 14.825 33.048 ;
     RECT  13.504 35.856 14.861 38.568 ;
     RECT  13.504 34.176 14.893 34.584 ;
     RECT  14.861 35.856 14.893 37.848 ;
     RECT  14.641 39.744 15.001 39.768 ;
     RECT  14.893 34.176 15.013 37.848 ;
     RECT  14.569 46.128 15.505 51.864 ;
     RECT  15.001 38.976 15.901 39.768 ;
     RECT  14.929 32.208 15.908 32.52 ;
     RECT  15.013 33.6 15.908 37.848 ;
     RECT  15.901 38.976 15.908 40.44 ;
     RECT  14.821 44.448 15.908 45.144 ;
     RECT  15.505 46.128 15.908 52.488 ;
     RECT  15.908 2.148 16.012 84.252 ;
     RECT  16.012 2.418 16.204 83.982 ;
     RECT  16.204 47.904 16.553 49.512 ;
     RECT  16.204 31.872 16.589 32.52 ;
     RECT  16.204 52.224 16.589 52.488 ;
     RECT  16.589 32.208 16.697 32.52 ;
     RECT  16.697 32.208 16.733 32.232 ;
     RECT  16.589 52.224 16.805 52.296 ;
     RECT  16.204 44.64 17.057 45.192 ;
     RECT  16.204 38.976 17.129 40.44 ;
     RECT  16.805 52.272 17.129 52.296 ;
     RECT  16.204 34.8 17.165 37.08 ;
     RECT  17.165 34.8 17.201 36.312 ;
     RECT  17.201 34.8 17.209 36.216 ;
     RECT  17.057 44.64 17.309 45.144 ;
     RECT  16.553 47.904 17.341 49.272 ;
     RECT  16.204 50.784 17.345 50.808 ;
     RECT  17.129 39.264 17.521 40.44 ;
     RECT  17.209 34.944 17.561 36.216 ;
     RECT  16.204 29.904 17.989 29.928 ;
     RECT  17.309 44.64 18.277 44.664 ;
     RECT  17.561 34.944 18.313 36.024 ;
     RECT  18.169 43.296 18.313 43.32 ;
     RECT  18.277 44.64 18.313 45.576 ;
     RECT  17.521 39.264 18.349 40.92 ;
     RECT  18.313 43.296 18.349 45.576 ;
     RECT  17.989 29.376 18.529 29.928 ;
     RECT  18.529 29.376 18.608 30.888 ;
     RECT  18.313 34.464 18.608 36.024 ;
     RECT  18.349 38.784 18.608 40.92 ;
     RECT  18.349 43.008 18.608 45.576 ;
     RECT  16.204 46.608 18.608 46.632 ;
     RECT  17.341 47.664 18.608 49.272 ;
     RECT  17.629 52.896 18.608 52.92 ;
     RECT  18.608 2.148 18.712 84.252 ;
     RECT  18.712 2.418 18.904 83.982 ;
     RECT  18.904 40.128 19.073 40.152 ;
     RECT  18.904 30.816 19.289 31.272 ;
     RECT  19.289 30.912 19.361 31.272 ;
     RECT  18.904 27.264 19.427 27.336 ;
     RECT  19.361 30.912 19.433 30.936 ;
     RECT  18.904 41.184 19.433 41.544 ;
     RECT  18.904 28.8 19.475 29.592 ;
     RECT  19.433 41.184 19.505 41.208 ;
     RECT  19.475 28.944 19.667 29.592 ;
     RECT  18.904 42.72 19.667 44.664 ;
     RECT  19.667 43.008 19.685 44.664 ;
     RECT  19.685 44.64 19.763 44.664 ;
     RECT  18.904 34.608 19.897 37.992 ;
     RECT  18.904 45.936 19.897 50.568 ;
     RECT  18.904 33.456 19.933 33.48 ;
     RECT  19.897 34.512 19.933 37.992 ;
     RECT  19.933 32.208 19.969 32.232 ;
     RECT  19.897 45.936 19.969 51.144 ;
     RECT  19.969 45.84 20.149 51.144 ;
     RECT  19.969 32.208 20.185 32.424 ;
     RECT  19.933 33.456 20.185 37.992 ;
     RECT  19.427 27.264 20.243 27.288 ;
     RECT  19.685 43.008 20.243 43.032 ;
     RECT  19.667 28.944 20.291 29.064 ;
     RECT  20.291 29.04 20.387 29.064 ;
     RECT  20.149 45.84 20.437 51.24 ;
     RECT  20.437 45.744 20.473 51.24 ;
     RECT  20.473 45.648 20.509 51.24 ;
     RECT  20.185 32.208 20.545 37.992 ;
     RECT  20.509 45.264 21.301 51.24 ;
     RECT  20.545 32.208 21.373 38.184 ;
     RECT  21.373 32.208 21.564 38.28 ;
     RECT  21.301 45.264 21.564 51.336 ;
    LAYER M5 ;
     RECT  2.4 2.137 2.52 2.151 ;
     RECT  5.1 2.137 5.22 2.151 ;
     RECT  7.8 2.137 7.92 2.151 ;
     RECT  10.5 2.137 10.62 2.151 ;
     RECT  13.2 2.137 13.32 2.151 ;
     RECT  15.9 2.137 16.02 2.151 ;
     RECT  18.6 2.137 18.72 2.151 ;
     RECT  18.6 2.151 18.912 27.301 ;
     RECT  20.208 27.253 20.232 27.301 ;
     RECT  18.6 27.301 20.232 28.933 ;
     RECT  18.6 28.933 20.28 29.029 ;
     RECT  18.6 29.029 20.376 29.365 ;
     RECT  15.9 2.151 16.212 29.893 ;
     RECT  18 29.365 20.376 29.893 ;
     RECT  15.9 29.893 20.376 33.589 ;
     RECT  5.1 2.151 5.412 34.357 ;
     RECT  7.8 2.151 8.112 34.357 ;
     RECT  6.864 34.357 8.112 34.547 ;
     RECT  15.024 33.589 20.376 34.549 ;
     RECT  4.272 34.357 5.412 34.741 ;
     RECT  14.832 34.549 20.376 34.835 ;
     RECT  4.272 34.741 6.024 35.317 ;
     RECT  18 34.835 20.376 35.363 ;
     RECT  14.832 34.835 16.212 35.411 ;
     RECT  18.6 35.363 20.376 35.603 ;
     RECT  13.2 2.151 13.512 35.845 ;
     RECT  14.832 35.411 14.856 35.845 ;
     RECT  18.6 35.603 19.512 35.939 ;
     RECT  18.6 35.939 19.464 36.035 ;
     RECT  13.104 35.845 14.856 36.515 ;
     RECT  18.6 36.035 19.416 36.515 ;
     RECT  4.128 35.317 6.024 36.997 ;
     RECT  10.5 2.151 10.812 36.997 ;
     RECT  14.832 36.515 14.856 37.571 ;
     RECT  0.192 37.813 0.216 38.003 ;
     RECT  3.936 36.997 6.024 38.435 ;
     RECT  4.272 38.435 6.024 39.203 ;
     RECT  15.9 35.411 16.212 39.493 ;
     RECT  15.36 39.493 16.212 39.779 ;
     RECT  0.144 39.013 0.168 40.355 ;
     RECT  4.272 39.203 5.784 41.171 ;
     RECT  4.272 41.171 5.412 41.221 ;
     RECT  7.8 34.547 8.112 42.133 ;
     RECT  3.84 41.221 5.412 42.275 ;
     RECT  18.6 36.515 18.912 42.709 ;
     RECT  6.816 42.133 8.112 42.803 ;
     RECT  18.6 42.709 19.656 42.997 ;
     RECT  18.6 42.997 20.232 43.285 ;
     RECT  2.4 2.151 2.712 43.669 ;
     RECT  4.176 42.275 5.412 43.669 ;
     RECT  15.9 39.779 16.212 44.869 ;
     RECT  15.9 44.869 17.016 45.011 ;
     RECT  0.192 41.989 0.216 45.541 ;
     RECT  0.192 45.541 0.312 45.733 ;
     RECT  13.2 36.515 13.512 46.117 ;
     RECT  15.9 45.011 16.212 46.213 ;
     RECT  0.192 45.733 0.36 46.835 ;
     RECT  13.2 46.117 13.656 47.029 ;
     RECT  10.32 36.997 10.812 47.075 ;
     RECT  13.104 47.029 13.656 47.075 ;
     RECT  15.408 46.213 16.212 47.315 ;
     RECT  2.4 43.669 5.412 47.939 ;
     RECT  0.192 46.835 0.216 48.083 ;
     RECT  18.192 43.285 20.232 48.275 ;
     RECT  18.192 48.275 19.656 48.467 ;
     RECT  18.192 48.467 18.912 48.515 ;
     RECT  2.4 47.939 3.672 48.901 ;
     RECT  13.104 47.075 13.512 48.997 ;
     RECT  14.88 48.421 14.904 49.235 ;
     RECT  2.304 48.901 3.672 49.525 ;
     RECT  4.8 47.939 5.412 49.525 ;
     RECT  13.056 48.997 13.512 49.571 ;
     RECT  13.104 49.571 13.512 49.811 ;
     RECT  2.304 49.525 5.412 50.291 ;
     RECT  2.304 50.291 3.432 50.339 ;
     RECT  4.8 50.291 5.412 50.771 ;
     RECT  2.4 50.339 3.432 51.347 ;
     RECT  5.1 50.771 5.412 52.261 ;
     RECT  5.1 52.261 5.544 53.075 ;
     RECT  2.4 51.347 2.712 84.249 ;
     RECT  5.1 53.075 5.412 84.249 ;
     RECT  7.8 42.803 8.112 84.249 ;
     RECT  10.5 47.075 10.812 84.249 ;
     RECT  13.2 49.811 13.512 84.249 ;
     RECT  15.9 47.315 16.212 84.249 ;
     RECT  18.6 48.515 18.912 84.249 ;
     RECT  2.4 84.249 2.52 84.263 ;
     RECT  5.1 84.249 5.22 84.263 ;
     RECT  7.8 84.249 7.92 84.263 ;
     RECT  10.5 84.249 10.62 84.263 ;
     RECT  13.2 84.249 13.32 84.263 ;
     RECT  15.9 84.249 16.02 84.263 ;
     RECT  18.6 84.249 18.72 84.263 ;
  END
END ot_qwen_tile_operand
END LIBRARY
